// Mitsubishi GX Works2 project: TR3FB_sample_AnticollisionRead   PLC: Q03UDV
// TR3FBサンプルプログラム シリアル接続 アンチコリジョン制御

PROGRAM MAIN
VAR
  Initial_1 : P+TAKAYA-TR3-C24_Initial;
  Response_1 : P+TAKAYA-TR3-C24_Response;
  Inventory2_1 : P+TAKAYA-TR3-C24_Inventory2;
  ReadBytes_1 : P+TAKAYA-TR3-C24_ReadBytes;
  CallBuzzer_1 : P+TAKAYA-TR3-C24_CallBuzzer;
  SetTransmitSig_1 : P+TAKAYA-TR3-C24_SetTransmitSig;
END_VAR
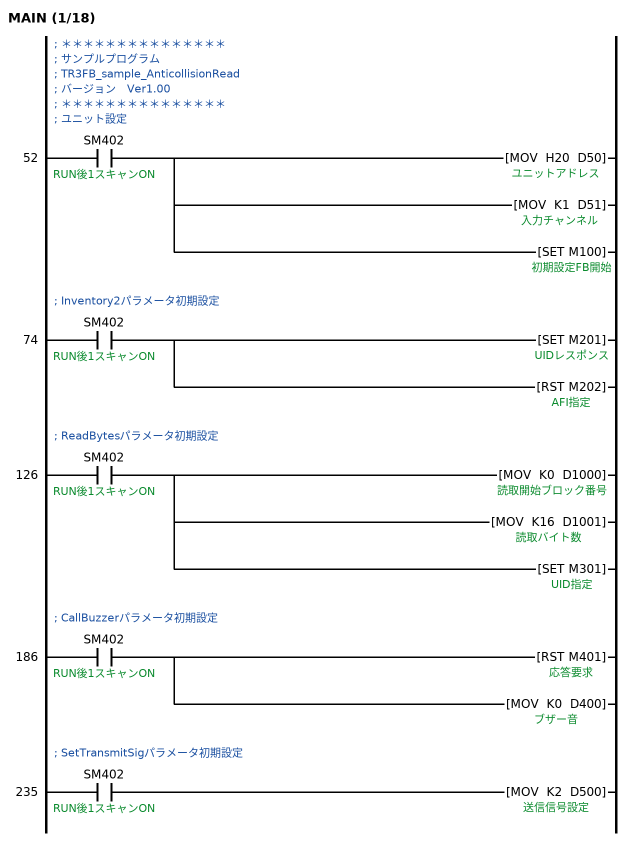
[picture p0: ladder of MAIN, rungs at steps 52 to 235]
; 
; ＊＊＊＊＊＊＊＊＊＊＊＊＊＊＊
; サンプルプログラム
; TR3FB_sample_AnticollisionRead
; バージョン　Ver1.00
; ＊＊＊＊＊＊＊＊＊＊＊＊＊＊＊
; ユニット設定
52    LD      SM402  ; RUN後1スキャンON
      MOV     H20 D50  ; ユニットアドレス
      MOV     K1 D51  ; 入力チャンネル
      SET     M100  ; 初期設定FB開始
; Inventory2パラメータ初期設定
74    LD      SM402  ; RUN後1スキャンON
      SET     M201  ; UIDレスポンス
        [note] UIDレスポンス：ON=UID数とUID
      RST     M202  ; AFI指定
        [note] AFI指定：OFF=AFI値を指定しない
; ReadBytesパラメータ初期設定
126   LD      SM402  ; RUN後1スキャンON
      MOV     K0 D1000  ; 読取開始ブロック番号
        [note] 読取開始ブロック番号=0
      MOV     K16 D1001  ; 読取バイト数
        [note] 読取バイト数=16
      SET     M301  ; UID指定
        [note] UID指定：ON=UIDを指定する
; CallBuzzerパラメータ初期設定
186   LD      SM402  ; RUN後1スキャンON
      RST     M401  ; 応答要求
        [note] 応答要求：OFF=応答を要求しない
      MOV     K0 D400  ; ブザー音
        [note] ブザー音=0/ピー
; SetTransmitSigパラメータ初期設定
235   LD      SM402  ; RUN後1スキャンON
      MOV     K2 D500  ; 送信信号設定
        [note] 送信信号設定：2=OFF→ON
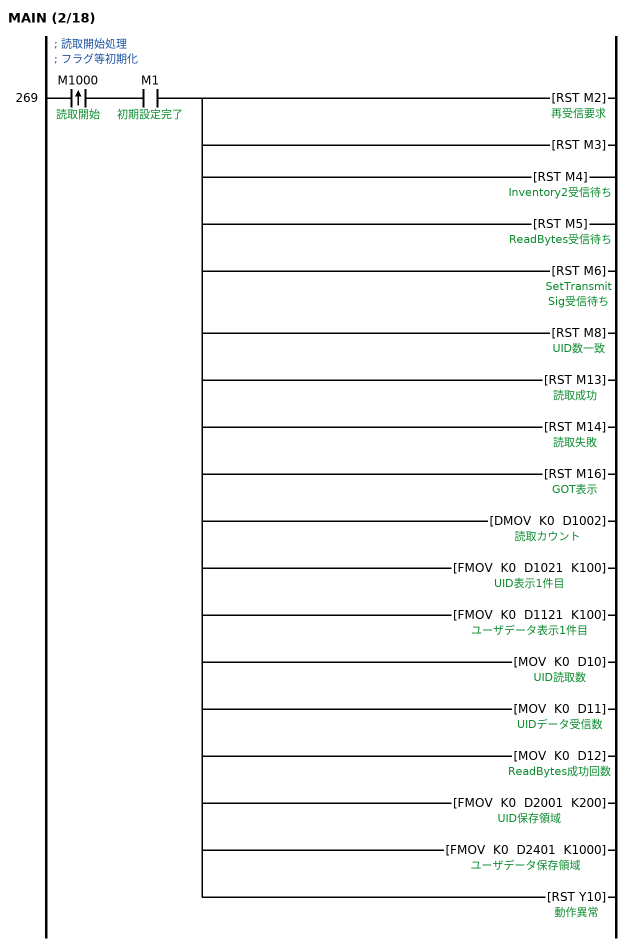
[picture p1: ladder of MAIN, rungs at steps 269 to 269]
; 読取開始処理
; フラグ等初期化
269   LDP     M1000  ; 読取開始
      AND     M1  ; 初期設定完了
      RST     M2  ; 再受信要求
        [note] 再受信要求フラグリセット
      RST     M3
        [note] 受信解析フラグリセット
      RST     M4  ; Inventory2受信待ち
        [note] Inventory2受信待ちフラグリセット
      RST     M5  ; ReadBytes受信待ち
        [note] ReadBytes受信待ちフラグリセット
      RST     M6  ; SetTransmitSig受信待ち
        [note] SetTrainsmitSigフラグリセット
      RST     M8  ; UID数一致
        [note] UID数一致フラグリセット
      RST     M13  ; 読取成功
        [note] 読取成功フラグリセット
      RST     M14  ; 読取失敗
        [note] 読取失敗フラグリセット
      RST     M16  ; GOT表示
        [note] GOT表示フラグリセット
      DMOV    K0 D1002  ; 読取カウント
        [note] GOT読取枚数表示クリア
      FMOV    K0 D1021 K100  ; UID表示1件目
        [note] GOT_UID表示領域クリア
      FMOV    K0 D1121 K100  ; ユーザデータ表示1件目
        [note] GOT_ユーザデータ表示領域クリア
      MOV     K0 D10  ; UID読取数
        [note] UID読取数クリア
      MOV     K0 D11  ; UIDデータ受信数
        [note] UIDデータ受信数クリア
      MOV     K0 D12  ; ReadBytes成功回数
        [note] ReadBytes成功回数クリア
      FMOV    K0 D2001 K200  ; UID保存領域
        [note] UID保存領域クリア
      FMOV    K0 D2401 K1000  ; ユーザデータ保存領域
        [note] ユーザデータ保存領域クリア
      RST     Y10  ; 動作異常
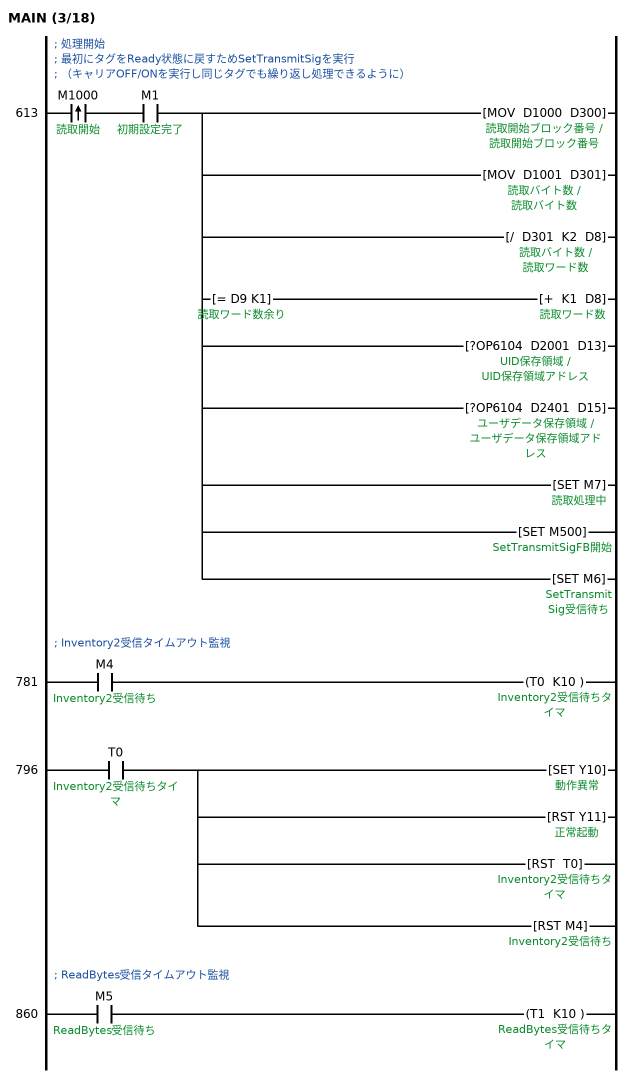
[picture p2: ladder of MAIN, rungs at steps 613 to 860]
; 処理開始
; 最初にタグをReady状態に戻すためSetTransmitSigを実行
; （キャリアOFF/ONを実行し同じタグでも繰り返し処理できるように）
613   LDP     M1000  ; 読取開始
      AND     M1  ; 初期設定完了
      MOV     D1000 D300  ; 読取開始ブロック番号
        [note] 読取開始ブロック番号再設定
      MOV     D1001 D301  ; 読取バイト数
        [note] 読取バイト数再設定
      /       D301 K2 D8  ; 読取ワード数
        [note] 読取バイト数から読取ワード数算出
      MPS
      AND=    D9 K1  ; 読取ワード数余り
      +       K1 D8
        [note] 余りがあれば1加える
      MPP
      ?OP6104 D2001 D13  ; UID保存領域アドレス
        [note] UID保存領域アドレス初期化
      ?OP6104 D2401 D15  ; ユーザデータ保存領域アドレス
        [note] ユーザデータ保存アドレス初期化
      SET     M7  ; 読取処理中
        [note] 読取処理中フラグセット
      SET     M500  ; SetTransmitSigFB開始
        [note] SetTransmitSig実行
      SET     M6  ; SetTransmitSig受信待ち
        [note] 受信待ちフラグセット
; Inventory2受信タイムアウト監視
781   LD      M4  ; Inventory2受信待ち
      OUT     T0 K10  ; Inventory2受信待ちタイマ
        [note] タイマ1秒に設定
796   LD      T0  ; Inventory2受信待ちタイマ
      SET     Y10  ; 動作異常
        [note] 動作異常：セット
      RST     Y11  ; 正常起動
        [note] 正常動作：リセット
      RST     T0  ; Inventory2受信待ちタイマ
        [note] タイマリセット
      RST     M4  ; Inventory2受信待ち
        [note] フラグリセット
; ReadBytes受信タイムアウト監視
860   LD      M5  ; ReadBytes受信待ち
      OUT     T1 K10  ; ReadBytes受信待ちタイマ
        [note] タイマ1秒に設定
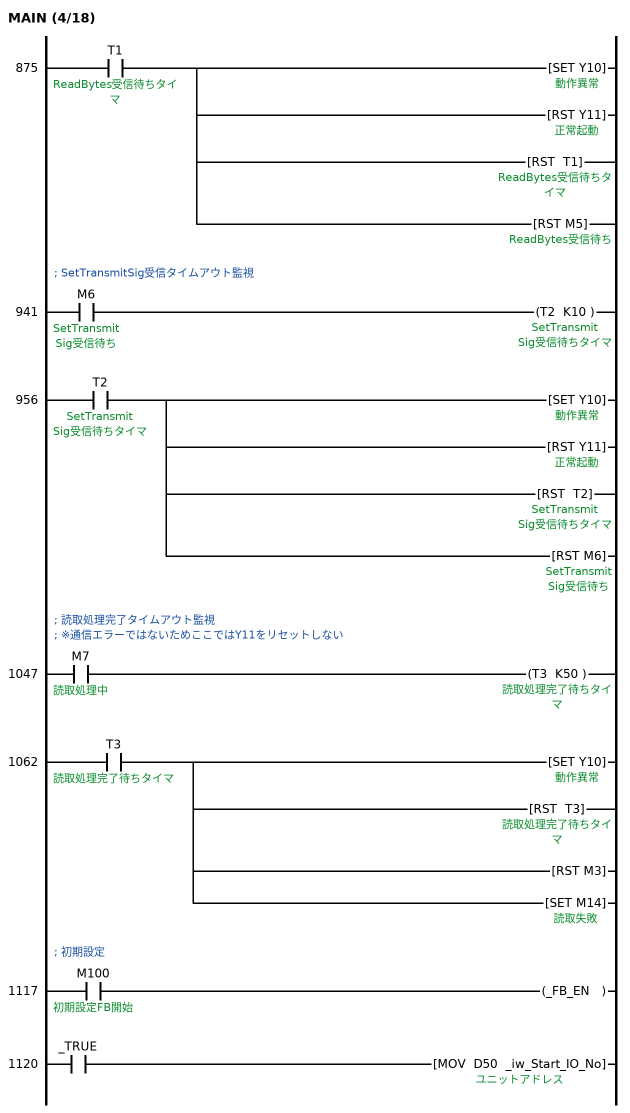
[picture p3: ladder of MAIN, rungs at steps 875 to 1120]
875   LD      T1  ; ReadBytes受信待ちタイマ
      SET     Y10  ; 動作異常
        [note] 動作異常：セット
      RST     Y11  ; 正常起動
        [note] 正常起動：リセット
      RST     T1  ; ReadBytes受信待ちタイマ
        [note] タイマリセット
      RST     M5  ; ReadBytes受信待ち
        [note] フラグリセット
; SetTransmitSig受信タイムアウト監視
941   LD      M6  ; SetTransmitSig受信待ち
      OUT     T2 K10  ; SetTransmitSig受信待ちタイマ
        [note] タイマ1秒に設定
956   LD      T2  ; SetTransmitSig受信待ちタイマ
      SET     Y10  ; 動作異常
        [note] 動作異常：セット
      RST     Y11  ; 正常起動
        [note] 正常起動：リセット
      RST     T2  ; SetTransmitSig受信待ちタイマ
        [note] タイマリセット
      RST     M6  ; SetTransmitSig受信待ち
        [note] フラグリセット
; 読取処理完了タイムアウト監視
; ※通信エラーではないためここではY11をリセットしない
1047  LD      M7  ; 読取処理中
      OUT     T3 K50  ; 読取処理完了待ちタイマ
        [note] タイマ5秒に設定
1062  LD      T3  ; 読取処理完了待ちタイマ
      SET     Y10  ; 動作異常
        [note] 動作異常：セット
      RST     T3  ; 読取処理完了待ちタイマ
        [note] タイマリセット
      RST     M3
        [note] フラグリセット
      SET     M14  ; 読取失敗
        [note] 読取失敗：セット
; FB BLK START P+TAKAYA-TR3-C24_Initial(Initial_1)
; 
; 初期設定
1117  LD      M100  ; 初期設定FB開始
      OUT     _FB_EN
1120  LD      _TRUE
      MOV     D50 _iw_Start_IO_No
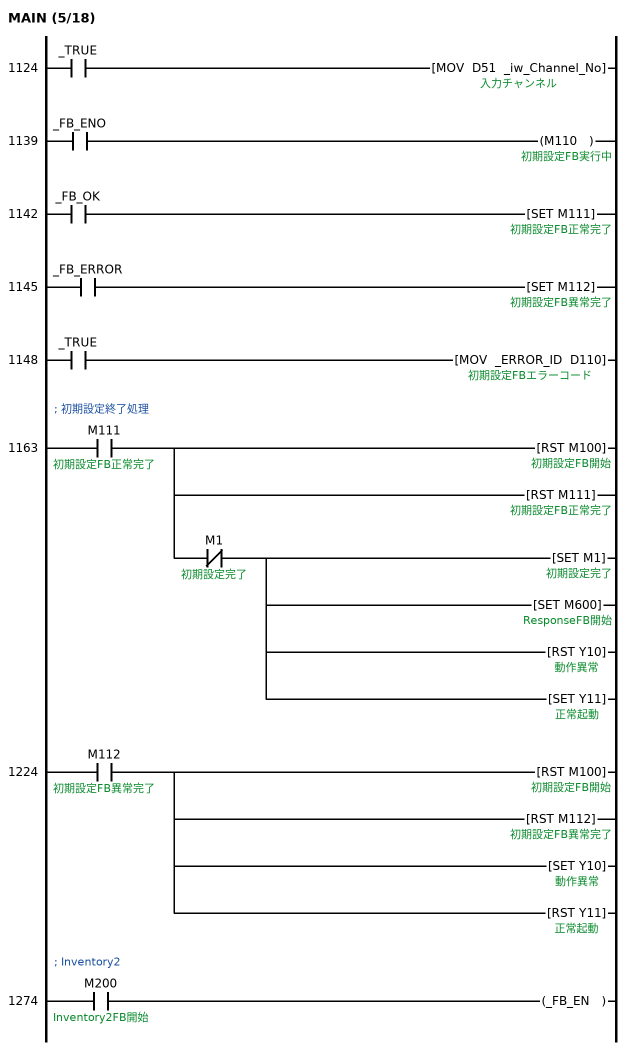
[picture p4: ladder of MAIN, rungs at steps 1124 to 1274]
1124  LD      _TRUE
      MOV     D51 _iw_Channel_No
; FB START
; FB_NAME P+TAKAYA-TR3-C24_Initial
; INSTANCE_NAME Initial_1
; FB IN_B:FB_EN
; FB OUT_FB_ENO:B
; FB IN_W:iw_Start_IO_No
; FB OUT_FB_OK:B
; FB IN_W:iw_Channel_No
; FB OUT_FB_ERROR:B
; FB OUT_ERROR_ID:W
; FB END
1139  LD      _FB_ENO
      OUT     M110  ; 初期設定FB実行中
1142  LD      _FB_OK
      SET     M111  ; 初期設定FB正常完了
1145  LD      _FB_ERROR
      SET     M112  ; 初期設定FB異常完了
1148  LD      _TRUE
      MOV     _ERROR_ID D110  ; 初期設定FBエラーコード
; FB BLK END
; 初期設定終了処理
1163  LD      M111  ; 初期設定FB正常完了
      RST     M100  ; 初期設定FB開始
        [note] FB動作停止
      RST     M111  ; 初期設定FB正常完了
        [note] フラグリセット
      ANI     M1  ; 初期設定完了
      SET     M1  ; 初期設定完了
        [note] 初期設定完了
      SET     M600  ; ResponseFB開始
        [note] 受信処理開始
      RST     Y10  ; 動作異常
        [note] 動作異常：リセット
      SET     Y11  ; 正常起動
        [note] 正常起動：セット
1224  LD      M112  ; 初期設定FB異常完了
      RST     M100  ; 初期設定FB開始
        [note] FB動作停止
      RST     M112  ; 初期設定FB異常完了
        [note] フラグリセット
      SET     Y10  ; 動作異常
        [note] 動作異常：セット
      RST     Y11  ; 正常起動
        [note] 動作正常：リセット
; FB BLK START P+TAKAYA-TR3-C24_Inventory2(Inventory2_1)
; Inventory2
1274  LD      M200  ; Inventory2FB開始
      OUT     _FB_EN
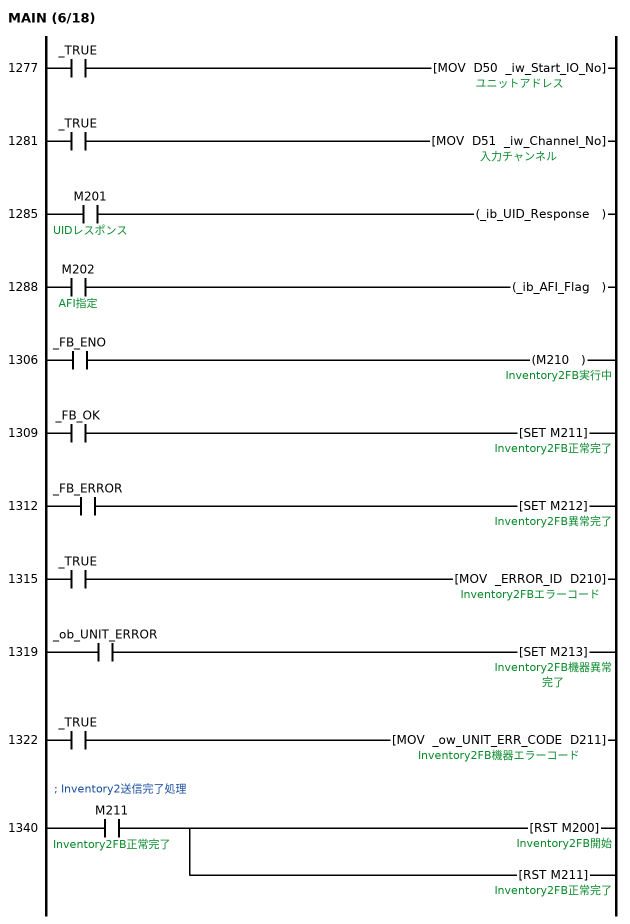
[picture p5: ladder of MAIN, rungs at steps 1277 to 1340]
1277  LD      _TRUE
      MOV     D50 _iw_Start_IO_No
1281  LD      _TRUE
      MOV     D51 _iw_Channel_No
1285  LD      M201  ; UIDレスポンス
      OUT     _ib_UID_Response
1288  LD      M202  ; AFI指定
      OUT     _ib_AFI_Flag
; FB START
; FB_NAME P+TAKAYA-TR3-C24_Inventory2
; INSTANCE_NAME Inventory2_1
; FB IN_B:FB_EN
; FB OUT_FB_ENO:B
; FB IN_W:iw_Start_IO_No
; FB OUT_FB_OK:B
; FB IN_W:iw_Channel_No
; FB OUT_FB_ERROR:B
; FB IN_B:ib_UID_Response
; FB OUT_ERROR_ID:W
; FB IN_B:ib_AFI_Flag
; FB OUT_ob_UNIT_ERROR:B
; FB OUT_ow_UNIT_ERR_CODE:W
; FB END
1306  LD      _FB_ENO
      OUT     M210  ; Inventory2FB実行中
1309  LD      _FB_OK
      SET     M211  ; Inventory2FB正常完了
1312  LD      _FB_ERROR
      SET     M212  ; Inventory2FB異常完了
1315  LD      _TRUE
      MOV     _ERROR_ID D210  ; Inventory2FBエラーコード
1319  LD      _ob_UNIT_ERROR
      SET     M213  ; Inventory2FB機器異常完了
1322  LD      _TRUE
      MOV     _ow_UNIT_ERR_CODE D211  ; Inventory2FB機器エラーコード
; FB BLK END
; Inventory2送信完了処理
1340  LD      M211  ; Inventory2FB正常完了
      RST     M200  ; Inventory2FB開始
        [note] FB動作停止
      RST     M211  ; Inventory2FB正常完了
        [note] フラグリセット
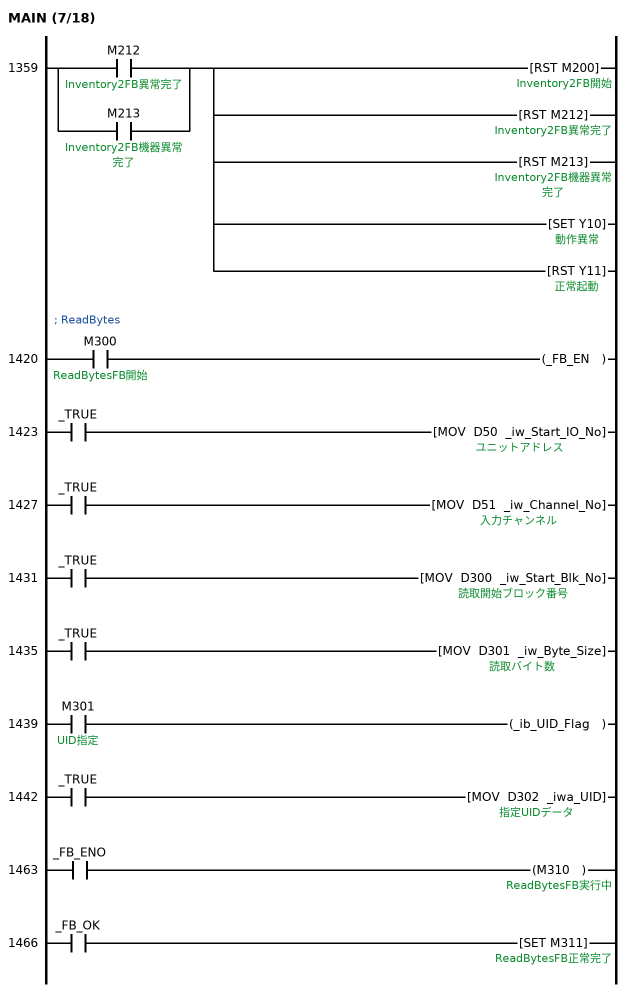
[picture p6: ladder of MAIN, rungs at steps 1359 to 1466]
1359  LD      M212  ; Inventory2FB異常完了
      OR      M213  ; Inventory2FB機器異常完了
      RST     M200  ; Inventory2FB開始
        [note] FB動作停止
      RST     M212  ; Inventory2FB異常完了
        [note] フラグリセット
      RST     M213  ; Inventory2FB機器異常完了
        [note] フラグリセット
      SET     Y10  ; 動作異常
        [note] 動作異常：セット
      RST     Y11  ; 正常起動
        [note] 正常起動：リセット
; FB BLK START P+TAKAYA-TR3-C24_ReadBytes(ReadBytes_1)
; ReadBytes
1420  LD      M300  ; ReadBytesFB開始
      OUT     _FB_EN
1423  LD      _TRUE
      MOV     D50 _iw_Start_IO_No
1427  LD      _TRUE
      MOV     D51 _iw_Channel_No
1431  LD      _TRUE
      MOV     D300 _iw_Start_Blk_No
1435  LD      _TRUE
      MOV     D301 _iw_Byte_Size
1439  LD      M301  ; UID指定
      OUT     _ib_UID_Flag
1442  LD      _TRUE
      MOV     D302 _iwa_UID  ; 指定UIDデータ
; FB START
; FB_NAME P+TAKAYA-TR3-C24_ReadBytes
; INSTANCE_NAME ReadBytes_1
; FB IN_B:FB_EN
; FB OUT_FB_ENO:B
; FB IN_W:iw_Start_IO_No
; FB OUT_FB_OK:B
; FB IN_W:iw_Channel_No
; FB OUT_FB_ERROR:B
; FB IN_W:iw_Start_Blk_No
; FB OUT_ERROR_ID:W
; FB IN_W:iw_Byte_Size
; FB OUT_ob_UNIT_ERROR:B
; FB IN_B:ib_UID_Flag
; FB OUT_ow_UNIT_ERR_CODE:W
; FB IN_W:iwa_UID
; FB END
1463  LD      _FB_ENO
      OUT     M310  ; ReadBytesFB実行中
1466  LD      _FB_OK
      SET     M311  ; ReadBytesFB正常完了
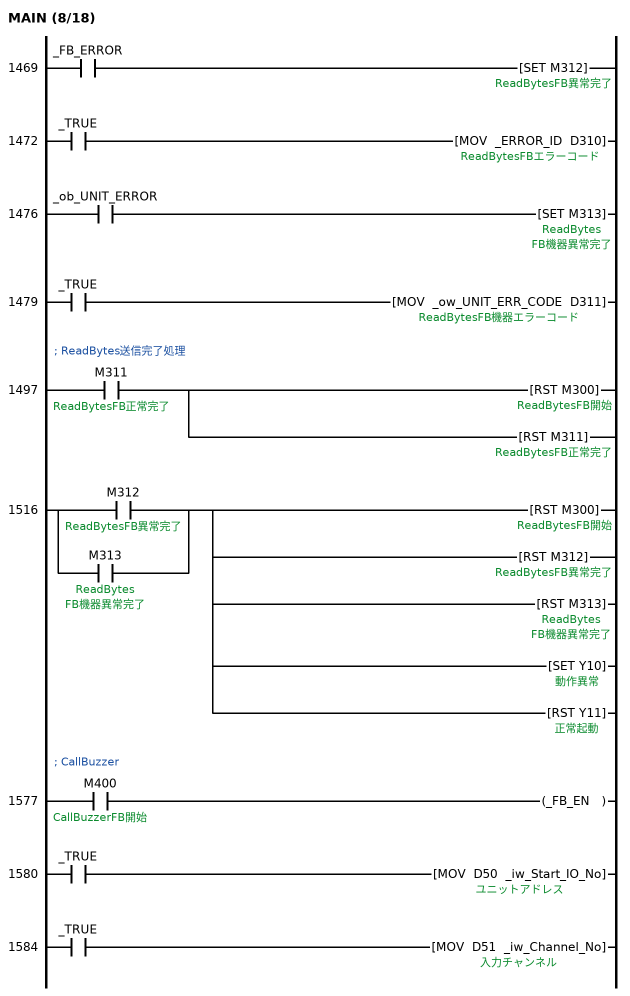
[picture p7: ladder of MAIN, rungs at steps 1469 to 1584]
1469  LD      _FB_ERROR
      SET     M312  ; ReadBytesFB異常完了
1472  LD      _TRUE
      MOV     _ERROR_ID D310  ; ReadBytesFBエラーコード
1476  LD      _ob_UNIT_ERROR
      SET     M313  ; ReadBytesFB機器異常完了
1479  LD      _TRUE
      MOV     _ow_UNIT_ERR_CODE D311  ; ReadBytesFB機器エラーコード
; FB BLK END
; ReadBytes送信完了処理
1497  LD      M311  ; ReadBytesFB正常完了
      RST     M300  ; ReadBytesFB開始
        [note] FB動作停止
      RST     M311  ; ReadBytesFB正常完了
        [note] フラグリセット
1516  LD      M312  ; ReadBytesFB異常完了
      OR      M313  ; ReadBytesFB機器異常完了
      RST     M300  ; ReadBytesFB開始
        [note] FB動作停止
      RST     M312  ; ReadBytesFB異常完了
        [note] フラグリセット
      RST     M313  ; ReadBytesFB機器異常完了
        [note] フラグリセット
      SET     Y10  ; 動作異常
        [note] 動作異常：セット
      RST     Y11  ; 正常起動
        [note] 正常起動：リセット
; FB BLK START P+TAKAYA-TR3-C24_CallBuzzer(CallBuzzer_1)
; CallBuzzer
1577  LD      M400  ; CallBuzzerFB開始
      OUT     _FB_EN
1580  LD      _TRUE
      MOV     D50 _iw_Start_IO_No
1584  LD      _TRUE
      MOV     D51 _iw_Channel_No
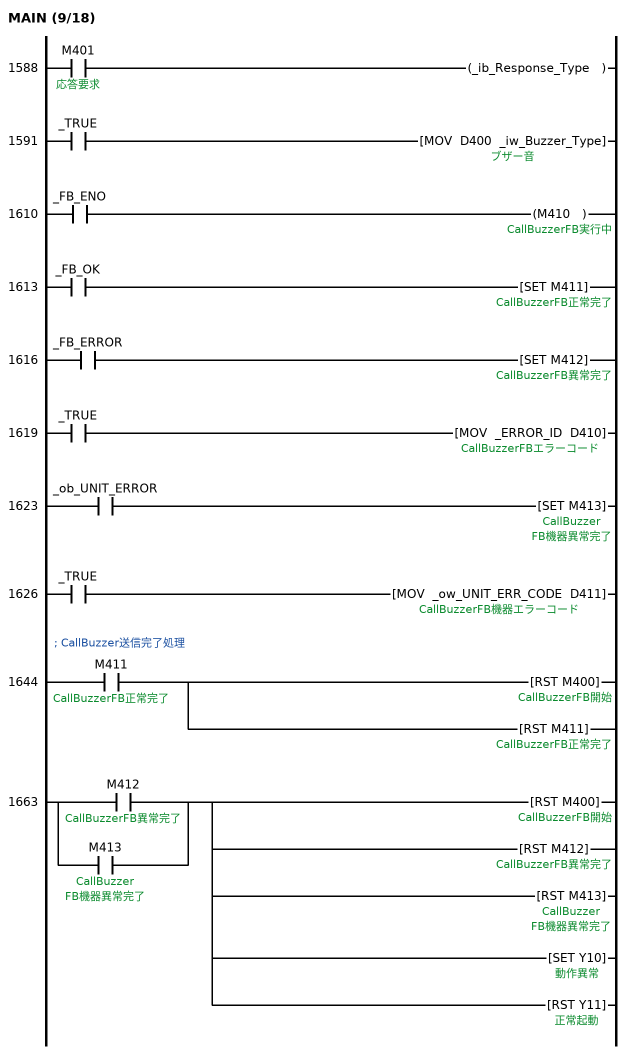
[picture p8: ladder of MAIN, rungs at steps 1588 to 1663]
1588  LD      M401  ; 応答要求
      OUT     _ib_Response_Type
1591  LD      _TRUE
      MOV     D400 _iw_Buzzer_Type
; FB START
; FB_NAME P+TAKAYA-TR3-C24_CallBuzzer
; INSTANCE_NAME CallBuzzer_1
; FB IN_B:FB_EN
; FB OUT_FB_ENO:B
; FB IN_W:iw_Start_IO_No
; FB OUT_FB_OK:B
; FB IN_W:iw_Channel_No
; FB OUT_FB_ERROR:B
; FB IN_B:ib_Response_Type
; FB OUT_ERROR_ID:W
; FB IN_W:iw_Buzzer_Type
; FB OUT_ob_UNIT_ERROR:B
; FB OUT_ow_UNIT_ERR_CODE:W
; FB END
1610  LD      _FB_ENO
      OUT     M410  ; CallBuzzerFB実行中
1613  LD      _FB_OK
      SET     M411  ; CallBuzzerFB正常完了
1616  LD      _FB_ERROR
      SET     M412  ; CallBuzzerFB異常完了
1619  LD      _TRUE
      MOV     _ERROR_ID D410  ; CallBuzzerFBエラーコード
1623  LD      _ob_UNIT_ERROR
      SET     M413  ; CallBuzzerFB機器異常完了
1626  LD      _TRUE
      MOV     _ow_UNIT_ERR_CODE D411  ; CallBuzzerFB機器エラーコード
; FB BLK END
; CallBuzzer送信完了処理
1644  LD      M411  ; CallBuzzerFB正常完了
      RST     M400  ; CallBuzzerFB開始
        [note] FB動作停止
      RST     M411  ; CallBuzzerFB正常完了
        [note] フラグリセット
1663  LD      M412  ; CallBuzzerFB異常完了
      OR      M413  ; CallBuzzerFB機器異常完了
      RST     M400  ; CallBuzzerFB開始
        [note] FB動作停止
      RST     M412  ; CallBuzzerFB異常完了
        [note] フラグリセット
      RST     M413  ; CallBuzzerFB機器異常完了
        [note] フラグリセット
      SET     Y10  ; 動作異常
        [note] 動作異常：セット
      RST     Y11  ; 正常起動
        [note] 正常起動：リセット
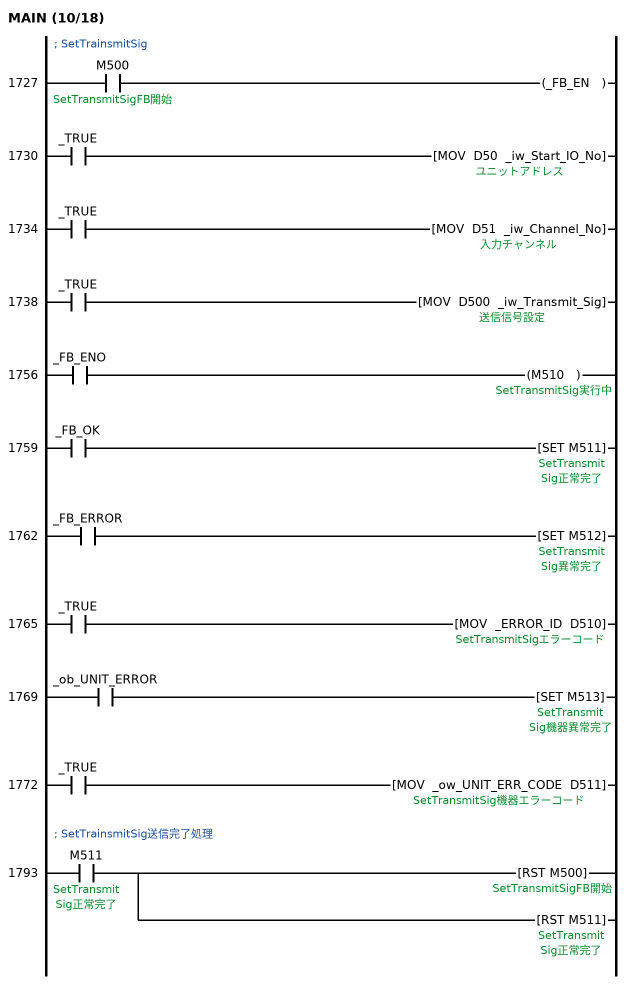
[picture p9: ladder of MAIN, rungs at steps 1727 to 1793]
; FB BLK START P+TAKAYA-TR3-C24_SetTransmitSig(SetTransmitSig_1)
; SetTrainsmitSig
1727  LD      M500  ; SetTransmitSigFB開始
      OUT     _FB_EN
1730  LD      _TRUE
      MOV     D50 _iw_Start_IO_No
1734  LD      _TRUE
      MOV     D51 _iw_Channel_No
1738  LD      _TRUE
      MOV     D500 _iw_Transmit_Sig
; FB START
; FB_NAME P+TAKAYA-TR3-C24_SetTransmitSig
; INSTANCE_NAME SetTransmitSig_1
; FB IN_B:FB_EN
; FB OUT_FB_ENO:B
; FB IN_W:iw_Start_IO_No
; FB OUT_FB_OK:B
; FB IN_W:iw_Channel_No
; FB OUT_FB_ERROR:B
; FB IN_W:iw_Transmit_Sig
; FB OUT_ERROR_ID:W
; FB OUT_ob_UNIT_ERROR:B
; FB OUT_ow_UNIT_ERR_CODE:W
; FB END
1756  LD      _FB_ENO
      OUT     M510  ; SetTransmitSig実行中
1759  LD      _FB_OK
      SET     M511  ; SetTransmitSig正常完了
1762  LD      _FB_ERROR
      SET     M512  ; SetTransmitSig異常完了
1765  LD      _TRUE
      MOV     _ERROR_ID D510  ; SetTransmitSigエラーコード
1769  LD      _ob_UNIT_ERROR
      SET     M513  ; SetTransmitSig機器異常完了
1772  LD      _TRUE
      MOV     _ow_UNIT_ERR_CODE D511  ; SetTransmitSig機器エラーコード
; FB BLK END
; SetTrainsmitSig送信完了処理
1793  LD      M511  ; SetTransmitSig正常完了
      RST     M500  ; SetTransmitSigFB開始
        [note] FB動作停止
      RST     M511  ; SetTransmitSig正常完了
        [note] フラグリセット
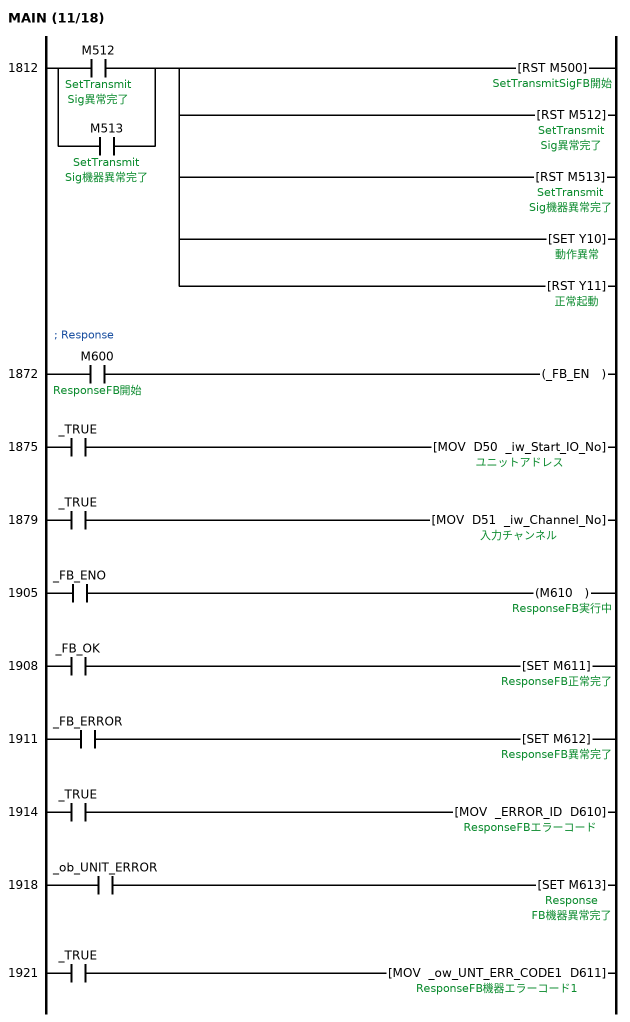
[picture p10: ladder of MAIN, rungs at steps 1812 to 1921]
1812  LD      M512  ; SetTransmitSig異常完了
      OR      M513  ; SetTransmitSig機器異常完了
      RST     M500  ; SetTransmitSigFB開始
        [note] FB動作停止
      RST     M512  ; SetTransmitSig異常完了
        [note] フラグリセット
      RST     M513  ; SetTransmitSig機器異常完了
        [note] フラグリセット
      SET     Y10  ; 動作異常
        [note] 動作異常：セット
      RST     Y11  ; 正常起動
        [note] 正常起動：リセット
; FB BLK START P+TAKAYA-TR3-C24_Response(Response_1)
; Response
1872  LD      M600  ; ResponseFB開始
      OUT     _FB_EN
1875  LD      _TRUE
      MOV     D50 _iw_Start_IO_No
1879  LD      _TRUE
      MOV     D51 _iw_Channel_No
; FB START
; FB_NAME P+TAKAYA-TR3-C24_Response
; INSTANCE_NAME Response_1
; FB IN_B:FB_EN
; FB OUT_FB_ENO:B
; FB IN_W:iw_Start_IO_No
; FB OUT_FB_OK:B
; FB IN_W:iw_Channel_No
; FB OUT_FB_ERROR:B
; FB OUT_ERROR_ID:W
; FB OUT_ob_UNIT_ERROR:B
; FB OUT_ow_UNT_ERR_CODE1:W
; FB OUT_ow_UNT_ERR_CODE2:W
; FB OUT_ow_RFID_Res_Type:W
; FB OUT_ow_RFID_ID:W
; FB OUT_ow_RFID_UID_Len:W
; FB OUT_ow_RFID_Data_Len:W
; FB OUT_ow_RFID_UII_Len:W
; FB OUT_owa_RFID_UID:W
; FB OUT_owa_RFID_Data:W
; FB OUT_owa_RFID_UII:W
; FB END
1905  LD      _FB_ENO
      OUT     M610  ; ResponseFB実行中
1908  LD      _FB_OK
      SET     M611  ; ResponseFB正常完了
1911  LD      _FB_ERROR
      SET     M612  ; ResponseFB異常完了
1914  LD      _TRUE
      MOV     _ERROR_ID D610  ; ResponseFBエラーコード
1918  LD      _ob_UNIT_ERROR
      SET     M613  ; ResponseFB機器異常完了
1921  LD      _TRUE
      MOV     _ow_UNT_ERR_CODE1 D611  ; ResponseFB機器エラーコード1
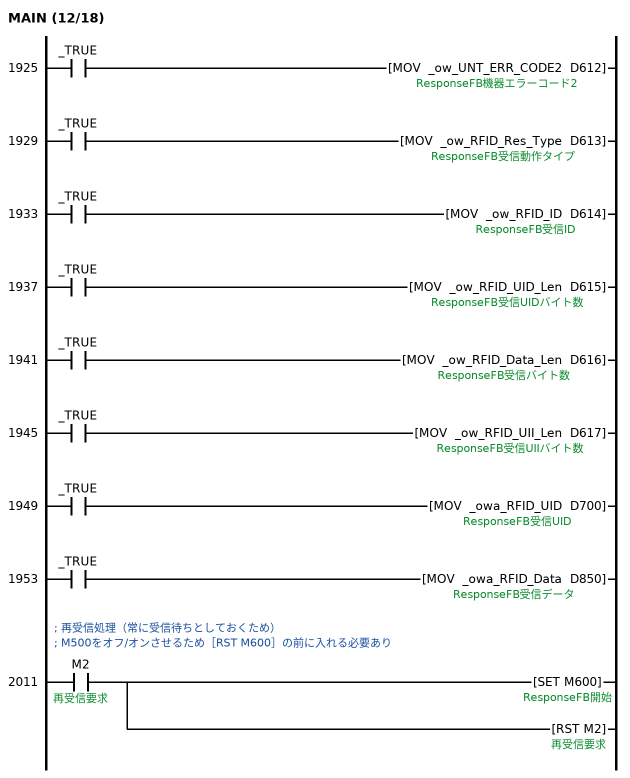
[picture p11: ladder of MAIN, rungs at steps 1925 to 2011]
1925  LD      _TRUE
      MOV     _ow_UNT_ERR_CODE2 D612  ; ResponseFB機器エラーコード2
1929  LD      _TRUE
      MOV     _ow_RFID_Res_Type D613  ; ResponseFB受信動作タイプ
1933  LD      _TRUE
      MOV     _ow_RFID_ID D614  ; ResponseFB受信ID
1937  LD      _TRUE
      MOV     _ow_RFID_UID_Len D615  ; ResponseFB受信UIDバイト数
1941  LD      _TRUE
      MOV     _ow_RFID_Data_Len D616  ; ResponseFB受信バイト数
1945  LD      _TRUE
      MOV     _ow_RFID_UII_Len D617  ; ResponseFB受信UIIバイト数
1949  LD      _TRUE
      MOV     _owa_RFID_UID D700  ; ResponseFB受信UID
1953  LD      _TRUE
      MOV     _owa_RFID_Data D850  ; ResponseFB受信データ
; FB BLK END
; 再受信処理（常に受信待ちとしておくため）
; M500をオフ/オンさせるため［RST M600］の前に入れる必要あり
2011  LD      M2  ; 再受信要求
      SET     M600  ; ResponseFB開始
        [note] ResponseFB開始
      RST     M2  ; 再受信要求
        [note] フラグリセット
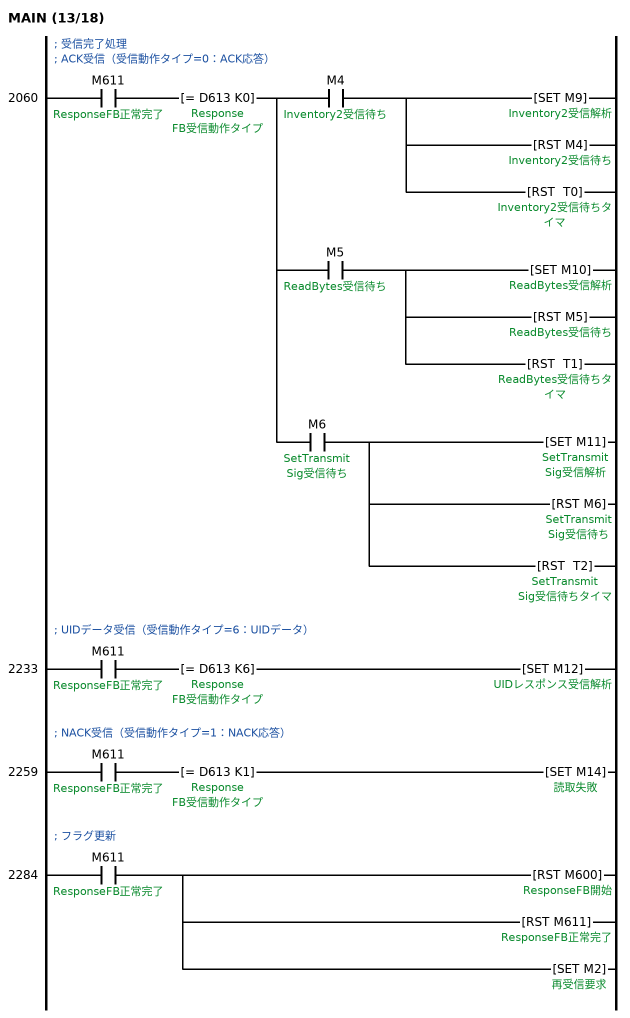
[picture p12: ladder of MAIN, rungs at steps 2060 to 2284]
; 受信完了処理
; ACK受信（受信動作タイプ=0：ACK応答）
2060  LD      M611  ; ResponseFB正常完了
      AND=    D613 K0  ; ResponseFB受信動作タイプ
      MPS
      AND     M4  ; Inventory2受信待ち
      SET     M9  ; Inventory2受信解析
        [note] Inventory2受信解析：セット
      RST     M4  ; Inventory2受信待ち
        [note] フラグリセット
      RST     T0  ; Inventory2受信待ちタイマ
        [note] 正常処理のためタイマリセット
      MRD
      AND     M5  ; ReadBytes受信待ち
      SET     M10  ; ReadBytes受信解析
        [note] ReadBytes受信解析：セット
      RST     M5  ; ReadBytes受信待ち
        [note] フラグリセット
      RST     T1  ; ReadBytes受信待ちタイマ
        [note] 正常処理のためタイマリセット
      MPP
      AND     M6  ; SetTransmitSig受信待ち
      SET     M11  ; SetTransmitSig受信解析
        [note] SetTransmitSig受信解析：セット
      RST     M6  ; SetTransmitSig受信待ち
        [note] フラグリセット
      RST     T2  ; SetTransmitSig受信待ちタイマ
        [note] 正常処理のためタイマクリア
; UIDデータ受信（受信動作タイプ=6：UIDデータ）
2233  LD      M611  ; ResponseFB正常完了
      AND=    D613 K6  ; ResponseFB受信動作タイプ
      SET     M12  ; UIDレスポンス受信解析
; NACK受信（受信動作タイプ=1：NACK応答）
2259  LD      M611  ; ResponseFB正常完了
      AND=    D613 K1  ; ResponseFB受信動作タイプ
      SET     M14  ; 読取失敗
        [note] 読取失敗フラグ：セット
; フラグ更新
2284  LD      M611  ; ResponseFB正常完了
      RST     M600  ; ResponseFB開始
        [note] FB動作停止
      RST     M611  ; ResponseFB正常完了
        [note] フラグリセット
      SET     M2  ; 再受信要求
        [note] 再受信要求フラグ：セット
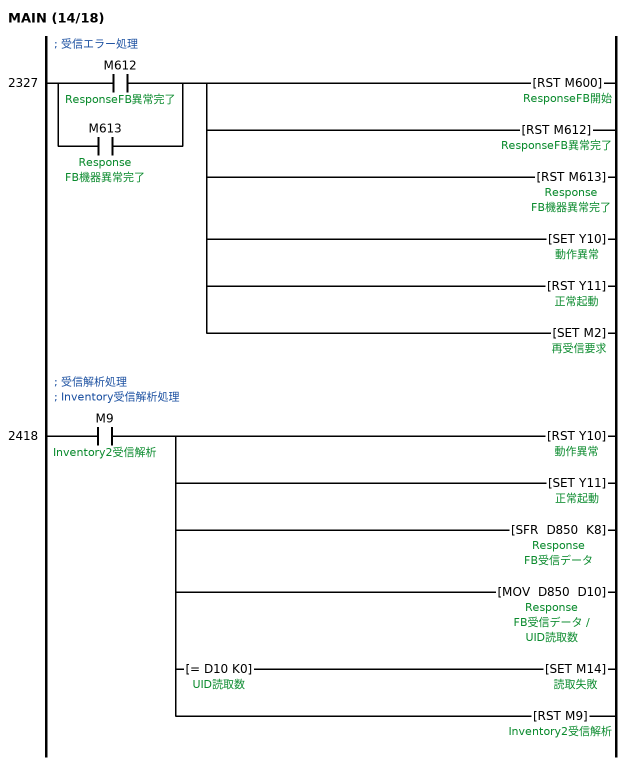
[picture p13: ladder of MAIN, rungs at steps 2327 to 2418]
; 受信エラー処理
2327  LD      M612  ; ResponseFB異常完了
      OR      M613  ; ResponseFB機器異常完了
      RST     M600  ; ResponseFB開始
        [note] FB動作停止
      RST     M612  ; ResponseFB異常完了
        [note] フラグリセット
      RST     M613  ; ResponseFB機器異常完了
        [note] フラグリセット
      SET     Y10  ; 動作異常
        [note] 動作異常：セット
      RST     Y11  ; 正常起動
        [note] 正常起動：リセット
      SET     M2  ; 再受信要求
        [note] 再受信要求フラグ：セット
; 
; 受信解析処理
; Inventory受信解析処理
2418  LD      M9  ; Inventory2受信解析
      RST     Y10  ; 動作異常
        [note] 動作異常：リセット
      SET     Y11  ; 正常起動
        [note] 正常動作：セット
      SFR     D850 K8
        [note] 受信データ2バイト目がUID読取数
      MOV     D850 D10
        [note] UID読取数設定
      MPS
      AND=    D10 K0  ; UID読取数
      SET     M14  ; 読取失敗
        [note] UID数=0のACKで読取失敗
      MPP
      RST     M9  ; Inventory2受信解析
        [note] フラグリセット
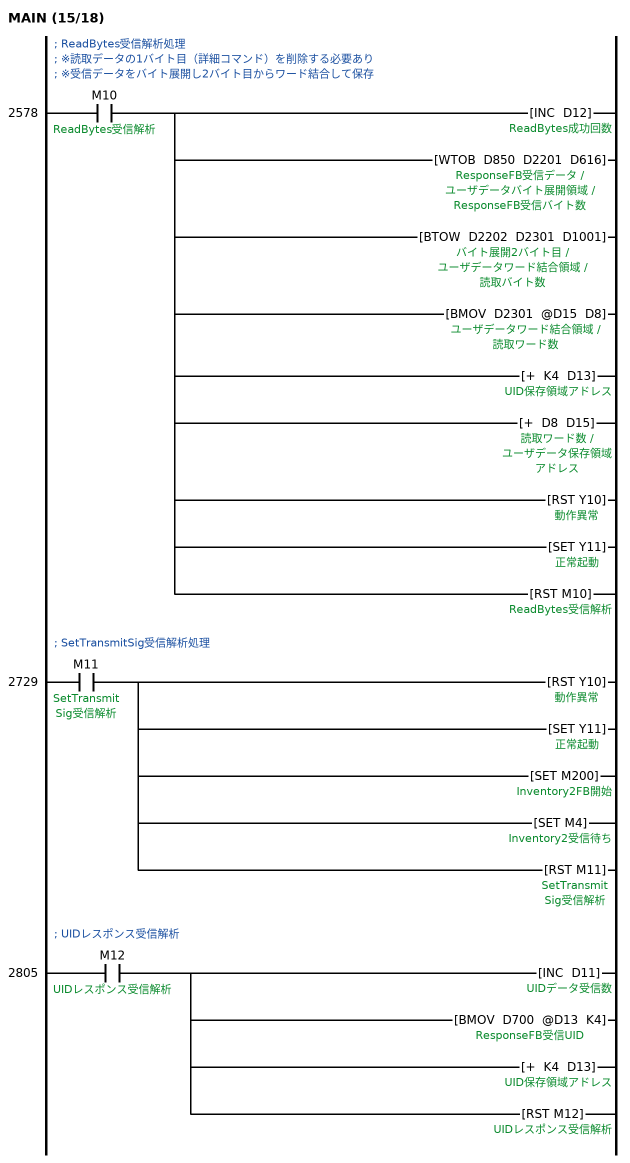
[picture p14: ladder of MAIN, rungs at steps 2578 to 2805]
; ReadBytes受信解析処理
; ※読取データの1バイト目（詳細コマンド）を削除する必要あり
; ※受信データをバイト展開し2バイト目からワード結合して保存
2578  LD      M10  ; ReadBytes受信解析
      INC     D12
        [note] 成功回数+1
      WTOB    D850 D2201 D616  ; ユーザデータバイト展開領域
        [note] 受信データをバイト展開
      BTOW    D2202 D2301 D1001  ; バイト展開2バイト目 / ユーザデータワード結合領域
        [note] 2バイト目から再度ワード結合
      BMOV    D2301 @D15 D8
        [note] 読取データを保存
      +       K4 D13
        [note] ReadBytesの指定UIDアドレスを次へ
      +       D8 D15
        [note] ユーザデータ保存先アドレスを次へ
      RST     Y10  ; 動作異常
        [note] 動作異常：リセット
      SET     Y11  ; 正常起動
        [note] 正常動作：セット
      RST     M10  ; ReadBytes受信解析
        [note] フラグリセット
; SetTransmitSig受信解析処理
2729  LD      M11  ; SetTransmitSig受信解析
      RST     Y10  ; 動作異常
        [note] 動作異常：リセット
      SET     Y11  ; 正常起動
        [note] 正常動作：セット
      SET     M200  ; Inventory2FB開始
        [note] Inventory2実行
      SET     M4  ; Inventory2受信待ち
        [note] Inventory2受信待ちフラグ：セット
      RST     M11  ; SetTransmitSig受信解析
        [note] フラグリセット
; UIDレスポンス受信解析
2805  LD      M12  ; UIDレスポンス受信解析
      INC     D11
        [note] UIDデータ受信数+1
      BMOV    D700 @D13 K4
        [note] UIDデータを保存
      +       K4 D13
        [note] UID保存領域アドレス+4
      RST     M12  ; UIDレスポンス受信解析
        [note] フラグリセット
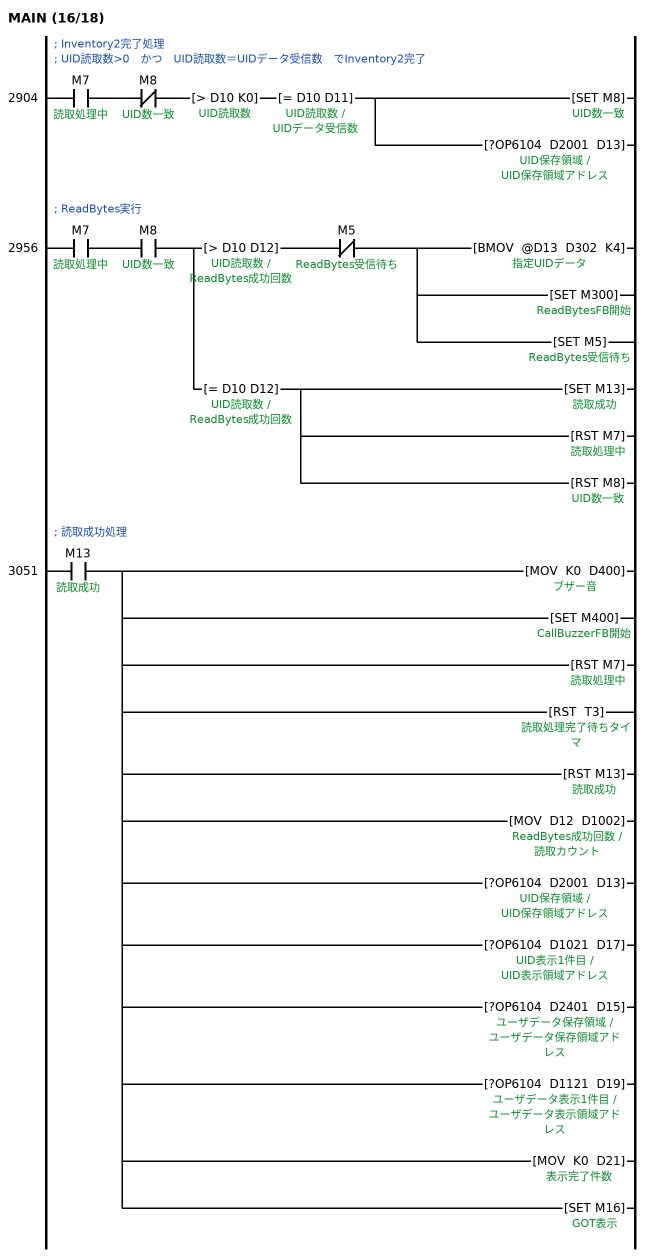
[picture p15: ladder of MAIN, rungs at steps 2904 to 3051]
; Inventory2完了処理
; UID読取数>0　かつ　UID読取数＝UIDデータ受信数　でInventory2完了
2904  LD      M7  ; 読取処理中
      ANI     M8  ; UID数一致
      AND>    D10 K0  ; UID読取数
      AND=    D10 D11  ; UID読取数 / UIDデータ受信数
      SET     M8  ; UID数一致
        [note] UID数一致フラグ：セット
      ?OP6104 D2001 D13
        [note] UID保存領域アドレスを元に戻す
; ReadBytes実行
2956  LD      M7  ; 読取処理中
      AND     M8  ; UID数一致
      MPS
      AND>    D10 D12  ; UID読取数 / ReadBytes成功回数
      ANI     M5  ; ReadBytes受信待ち
      BMOV    @D13 D302 K4
        [note] 指定UIDを設定
      SET     M300  ; ReadBytesFB開始
        [note] ReadBytes実行
      SET     M5  ; ReadBytes受信待ち
        [note] ReadBytes受信待ちフラグ：セット
      MPP
      AND=    D10 D12  ; UID読取数 / ReadBytes成功回数
      SET     M13  ; 読取成功
        [note] 読取成功フラグ：セット
      RST     M7  ; 読取処理中
        [note] フラグリセット
      RST     M8  ; UID数一致
        [note] フラグリセット
; 読取成功処理
3051  LD      M13  ; 読取成功
      MOV     K0 D400
        [note] ブザー音=0/ピー
      SET     M400  ; CallBuzzerFB開始
        [note] CallBuzzer実行
      RST     M7  ; 読取処理中
        [note] フラグリセット
      RST     T3  ; 読取処理完了待ちタイマ
        [note] タイマリセット
      RST     M13  ; 読取成功
        [note] フラグリセット
      MOV     D12 D1002
        [note] 読取カウント更新
      ?OP6104 D2001 D13
        [note] UID保存領域アドレス先頭指定
      ?OP6104 D1021 D17  ; UID表示領域アドレス
        [note] UID表示領域アドレス先頭指定
      ?OP6104 D2401 D15
        [note] ユーザ保存領域アドレス先頭指定
      ?OP6104 D1121 D19  ; ユーザデータ表示領域アドレス
        [note] ユーザ表示領域アドレス先頭指定
      MOV     K0 D21  ; 表示完了件数
        [note] 表示完了件数クリア
      SET     M16  ; GOT表示
        [note] GOT表示フラグ：セット
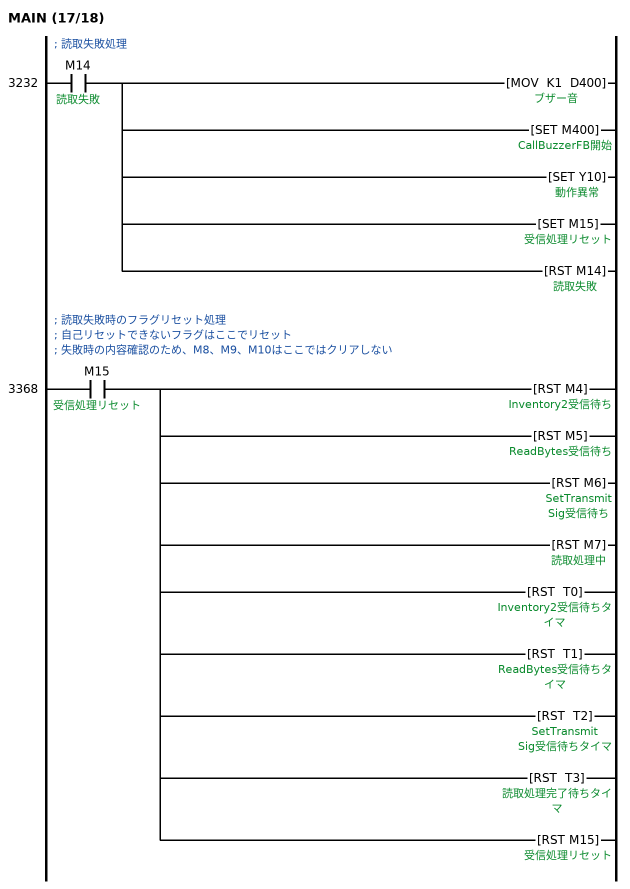
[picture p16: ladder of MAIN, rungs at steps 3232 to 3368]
; 読取失敗処理
3232  LD      M14  ; 読取失敗
      MOV     K1 D400
        [note] ブザー音=1/ピッピッピ
      SET     M400  ; CallBuzzerFB開始
        [note] CallBuzzer実行
      SET     Y10  ; 動作異常
        [note] 動作異常：セット
      SET     M15  ; 受信処理リセット
        [note] 受信処理リセットフラグ：セット
      RST     M14  ; 読取失敗
        [note] フラグリセット
; 読取失敗時のフラグリセット処理
; 自己リセットできないフラグはここでリセット
; 失敗時の内容確認のため、M8、M9、M10はここではクリアしない
3368  LD      M15  ; 受信処理リセット
      RST     M4  ; Inventory2受信待ち
        [note] フラグリセット
      RST     M5  ; ReadBytes受信待ち
        [note] フラグリセット
      RST     M6  ; SetTransmitSig受信待ち
        [note] フラグリセット
      RST     M7  ; 読取処理中
        [note] フラグリセット
      RST     T0  ; Inventory2受信待ちタイマ
      RST     T1  ; ReadBytes受信待ちタイマ
        [note] タイマリセット
      RST     T2  ; SetTransmitSig受信待ちタイマ
        [note] タイマリセット
      RST     T3  ; 読取処理完了待ちタイマ
        [note] タイマリセット
      RST     M15  ; 受信処理リセット
        [note] フラグリセット
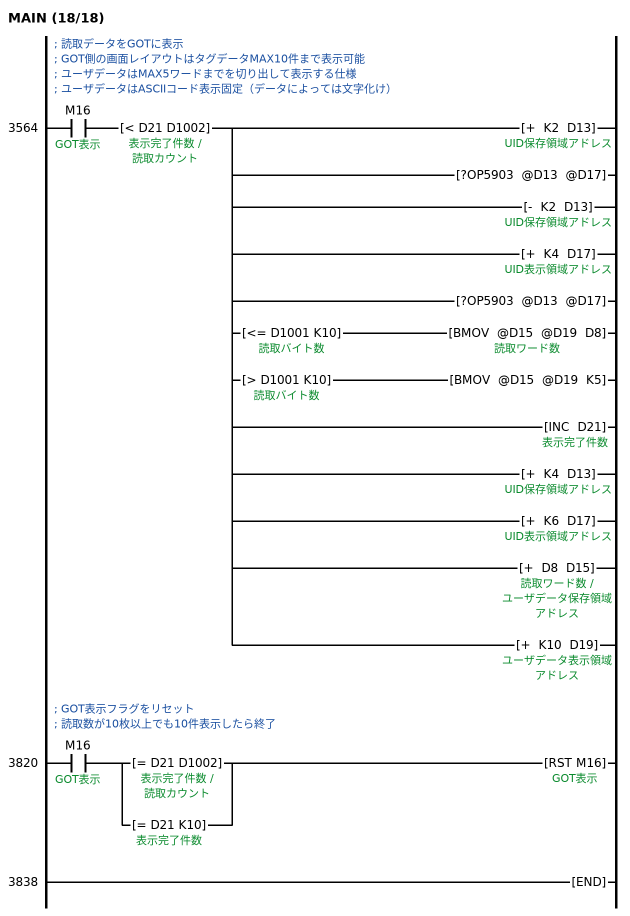
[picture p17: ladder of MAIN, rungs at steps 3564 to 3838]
; 読取データをGOTに表示
; GOT側の画面レイアウトはタグデータMAX10件まで表示可能
; ユーザデータはMAX5ワードまでを切り出して表示する仕様
; ユーザデータはASCIIコード表示固定（データによっては文字化け）
3564  LD      M16  ; GOT表示
      AND<    D21 D1002  ; 表示完了件数 / 読取カウント
      +       K2 D13
        [note] UID保存アドレスを上位側に移動
      ?OP5903 @D13 @D17
        [note] UID表示/上位4バイト
      -       K2 D13
        [note] UID保存アドレスを下位側に戻す
      +       K4 D17
        [note] UID表示アドレス+4
      ?OP5903 @D13 @D17
        [note] UID表示/下位4バイト
      MPS
      AND<=   D1001 K10  ; 読取バイト数
      BMOV    @D15 @D19 D8
        [note] ユーザデータ表示：5ワード以下
      MRD
      AND>    D1001 K10  ; 読取バイト数
      BMOV    @D15 @D19 K5
        [note] ユーザデータ表示：5ワード超
      MPP
      INC     D21
        [note] 表示完了件数+1
      +       K4 D13
        [note] UID保存領域アドレス+4
      +       K6 D17
        [note] UID表示領域アドレス+6
      +       D8 D15
        [note] ユーザデータ保存アドレスを次へ
      +       K10 D19
        [note] ユーザデータ表示アドレスを次へ
; GOT表示フラグをリセット
; 読取数が10枚以上でも10件表示したら終了
3820  LD      M16  ; GOT表示
      LD=     D21 D1002  ; 表示完了件数 / 読取カウント
      OR=     D21 K10  ; 表示完了件数
      ANB
      RST     M16  ; GOT表示
        [note] フラグリセット
3838  END
END_PROGRAM

FUNCTION_BLOCK P+TAKAYA-TR3-C24_Initial  // 初期設定
VAR_INPUT
  FB_EN : BOOL;  (* 実行命令 *)
  iw_Start_IO_No : INT;  (* ユニット装着XYアドレス *)
  iw_Channel_No : INT;  (* 入力チャンネル *)
END_VAR
VAR_OUTPUT
  FB_ENO : BOOL;  (* 実行状態 *)
  FB_OK : BOOL;  (* 正常完了 *)
  FB_ERROR : BOOL;  (* 異常完了フラグ *)
  ERROR_ID : INT;  (* エラーコード *)
END_VAR
VAR
  vb_Program_Init : BOOL;  (* プログラム実行前初期化 *)
  vb_Check_Input : BOOL;  (* 入力範囲判定 *)
  vb_Module_Init : BOOL;  (* ユニット初期化 *)
  vb_Program_End : BOOL;  (* FB終了処理内部フラグ *)
  vb_Tmp_OK : BOOL;  (* FB完了内部フラグ *)
  vb_Tmp_Error : BOOL;  (* エラー内部フラグ *)
  vw_Start_IO_No_Tmp : INT;  (* ユニット装着XYアドレス内部 *)
  vw_Channel_No_Tmp : INT;  (* 入力チャンネル内部 *)
  vw_ZTmp1 : INT;  (* Zデバイス1内部 *)
  vw_ZTmp2 : INT;  (* Zデバイス2内部 *)
END_VAR
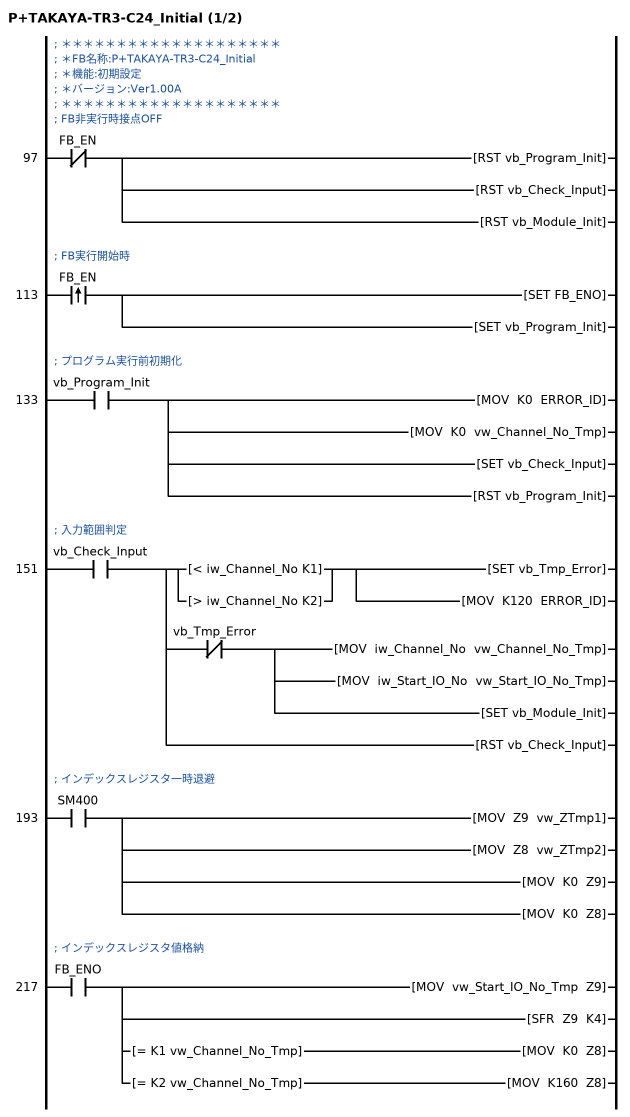
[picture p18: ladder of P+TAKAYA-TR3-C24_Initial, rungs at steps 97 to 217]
; ＊＊＊＊＊＊＊＊＊＊＊＊＊＊＊＊＊＊＊＊
; ＊FB名称:P+TAKAYA-TR3-C24_Initial
; ＊機能:初期設定
; ＊バージョン:Ver1.00A
; ＊＊＊＊＊＊＊＊＊＊＊＊＊＊＊＊＊＊＊＊
; FB非実行時接点OFF
97    LDI     FB_EN
      RST     vb_Program_Init
      RST     vb_Check_Input
      RST     vb_Module_Init
; FB実行開始時
113   LDP     FB_EN
      SET     FB_ENO
      SET     vb_Program_Init
; プログラム実行前初期化
133   LD      vb_Program_Init
      MOV     K0 ERROR_ID
      MOV     K0 vw_Channel_No_Tmp
      SET     vb_Check_Input
      RST     vb_Program_Init
; 入力範囲判定
151   LD      vb_Check_Input
      MPS
      LD<     iw_Channel_No K1
      OR>     iw_Channel_No K2
      ANB
      SET     vb_Tmp_Error
      MOV     K120 ERROR_ID
      MRD
      ANI     vb_Tmp_Error
      MOV     iw_Channel_No vw_Channel_No_Tmp
      MOV     iw_Start_IO_No vw_Start_IO_No_Tmp
      SET     vb_Module_Init
      MPP
      RST     vb_Check_Input
; インデックスレジスタ一時退避
193   LD      SM400
      MOV     Z9 vw_ZTmp1
      MOV     Z8 vw_ZTmp2
      MOV     K0 Z9
      MOV     K0 Z8
; インデックスレジスタ値格納
217   LD      FB_ENO
      MOV     vw_Start_IO_No_Tmp Z9
      SFR     Z9 K4
      MPS
      AND=    K1 vw_Channel_No_Tmp
      MOV     K0 Z8
      MPP
      AND=    K2 vw_Channel_No_Tmp
      MOV     K160 Z8
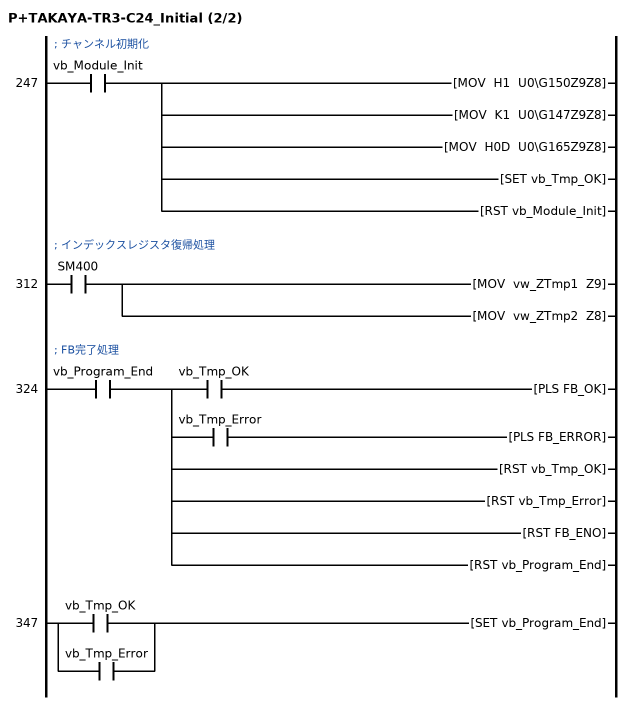
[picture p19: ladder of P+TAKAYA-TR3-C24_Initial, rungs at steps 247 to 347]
; チャンネル初期化
247   LD      vb_Module_Init
      MOV     H1 U0\G150Z9Z8
        [note] バイト単位指定
      MOV     K1 U0\G147Z9Z8
        [note] DC制御指定
      MOV     H0D U0\G165Z9Z8
        [note] 受信終了コード
      SET     vb_Tmp_OK
      RST     vb_Module_Init
; インデックスレジスタ復帰処理
312   LD      SM400
      MOV     vw_ZTmp1 Z9
      MOV     vw_ZTmp2 Z8
; FB完了処理
324   LD      vb_Program_End
      MPS
      AND     vb_Tmp_OK
      PLS     FB_OK
      MRD
      AND     vb_Tmp_Error
      PLS     FB_ERROR
      MPP
      RST     vb_Tmp_OK
      RST     vb_Tmp_Error
      RST     FB_ENO
      RST     vb_Program_End
347   LD      vb_Tmp_OK
      OR      vb_Tmp_Error
      SET     vb_Program_End
END_FUNCTION_BLOCK

FUNCTION_BLOCK P+TAKAYA-TR3-C24_Response  // 受信設定
VAR_INPUT
  FB_EN : BOOL;  (* 実行命令 *)
  iw_Start_IO_No : INT;  (* ユニット装着XYアドレス *)
END_VAR
VAR_OUTPUT
  FB_ENO : BOOL;  (* 実行状態 *)
  FB_OK : BOOL;  (* 正常完了 *)
  FB_ERROR : BOOL;  (* 異常完了フラグ *)
  ERROR_ID : INT;  (* エラーコード *)
  ob_UNIT_ERROR : BOOL;  (* 機器異常完了フラグ *)
  ow_UNT_ERR_CODE1 : INT;  (* 機器エラーコード1 *)
  ow_UNT_ERR_CODE2 : INT;  (* 機器エラーコード2 *)
  ow_RFID_Res_Type : INT;  (* 受信動作タイプ *)
  ow_RFID_ID : INT;  (* 受信ID *)
  ow_RFID_UID_Len : INT;  (* 受信UIDバイト数 *)
  ow_RFID_Data_Len : INT;  (* 受信バイト数 *)
  ow_RFID_UII_Len : INT;  (* 受信UIIバイト数 *)
  owa_RFID_UID : INT;  (* 受信UID *)
  owa_RFID_Data : INT;  (* 受信データ *)
  owa_RFID_UII : INT;  (* 受信UII *)
END_VAR
VAR
  vb_Tmp_OK : BOOL;  (* 正常完了内部フラグ *)
  vb_Tmp_Error : BOOL;  (* 異常完了内部フラグ *)
  vb_Tmp_Unit_Error : BOOL;  (* 機器異常完了内部フラグ *)
  vb_Program_Init : BOOL;  (* プログラム実行前初期化 *)
  vb_Check_Input : BOOL;  (* 入力範囲判定 *)
  vb_Check_Cmd : BOOL;  (* 受信コマンドチェック *)
  vb_UID_Cmd : BOOL;  (* UIDコマンド受信 *)
  vb_EPC_Cmd : BOOL;  (* EPCコマンド受信 *)
  vb_Other_Cmd : BOOL;  (* Otherコマンド受信 *)
  vb_Program_End : BOOL;  (* FB終了処理 *)
  vb_Receiving : BOOL;  (* 受信中フラグ *)
  vw_ZTmp1 : INT;  (* Zデバイス1内部 *)
  vd_DTmp1 : DINT;  (* 内部Dデバイス1 *)
  vd_DTmp2 : DINT;  (* 内部Dデバイス2 *)
  vd_DTmp3 : DINT;  (* 内部Dデバイス3 *)
  vd_DTmp4 : DINT;  (* 内部Dデバイス4 *)
  vba_Rcv : ARRAY [0..2] OF BOOL;  (* 受信処理 *)
  vb_Rcv_End : BOOL;  (* 受信処理終了 *)
  vb_Fin_Rcv : BOOL;  (* コマンド全データ受信終了 *)
  vd_Rcv_Pos : DINT;  (* 受信バッファ読出し位置 *)
  vwa_Rcv_Buf : ARRAY [0..130] OF INT;  (* 受信バッファ(ワード単位) *)
  vwa_Rcv_Data_Byte : ARRAY [0..261] OF INT;  (* 受信バッファ(バイト単位) *)
  vw_Received_Len : INT;  (* 受信済みデータ長 *)
  vw_Trans_Len : INT;  (* 受信データ長 *)
  vw_Fin_Rcv_Len : INT;  (* 受信データ長計算用 *)
  vw_Sum_Len : INT;  (* サム値計算用データ長 *)
  vw_Rcv_Sum : INT;  (* 受信サム値 *)
  vw_Channel_No_Tmp : INT;  (* 入力チャンネル内部 *)
  vw_Start_IO_No_Tmp : INT;  (* ユニット装着XYアドレス内部 *)
  vwa_Ctrl_Data : ARRAY [0..3] OF INT;  (* ダミーコントロールデータ *)
  vd_Calc_Dword : DINT;  (* ダブルワード計算用 *)
  vw_Etx_Ofs : INT;  (* ETXオフセット *)
  vw_Chk_TID_Len : INT;  (* TIDデータ長計算用 *)
END_VAR
VAR_INPUT
  iw_Channel_No : INT;  (* 入力チャンネル *)
END_VAR
VAR
  vw_ZTmp2 : INT;  (* Zデバイス2内部 *)
  vwa_Chk_Sum : ARRAY [0..1] OF INT;  (* サム計算値 *)
END_VAR
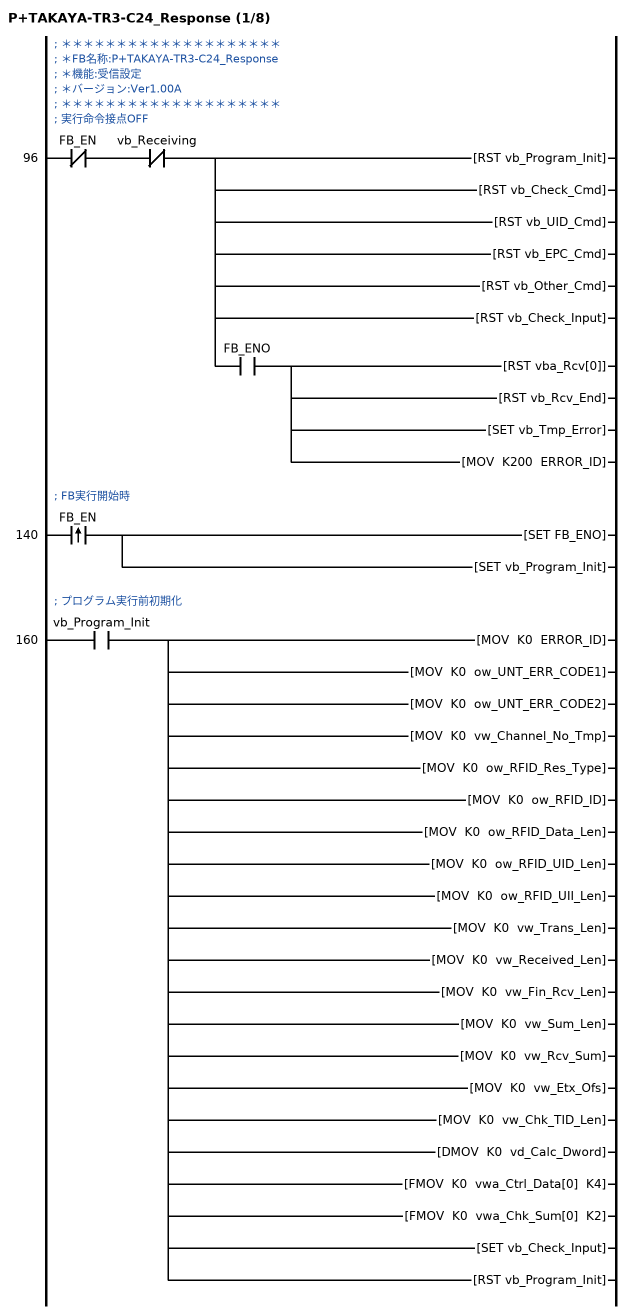
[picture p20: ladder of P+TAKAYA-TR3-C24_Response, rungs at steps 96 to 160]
; ＊＊＊＊＊＊＊＊＊＊＊＊＊＊＊＊＊＊＊＊
; ＊FB名称:P+TAKAYA-TR3-C24_Response
; ＊機能:受信設定
; ＊バージョン:Ver1.00A
; ＊＊＊＊＊＊＊＊＊＊＊＊＊＊＊＊＊＊＊＊
; 実行命令接点OFF
96    LDI     FB_EN
      ANI     vb_Receiving
      RST     vb_Program_Init
      RST     vb_Check_Cmd
      RST     vb_UID_Cmd
      RST     vb_EPC_Cmd
      RST     vb_Other_Cmd
      RST     vb_Check_Input
      AND     FB_ENO
      RST     vba_Rcv[0]
        [note] FB実行中強制終了
      RST     vb_Rcv_End
      SET     vb_Tmp_Error
      MOV     K200 ERROR_ID
; FB実行開始時
140   LDP     FB_EN
      SET     FB_ENO
      SET     vb_Program_Init
; プログラム実行前初期化
160   LD      vb_Program_Init
      MOV     K0 ERROR_ID
      MOV     K0 ow_UNT_ERR_CODE1
      MOV     K0 ow_UNT_ERR_CODE2
      MOV     K0 vw_Channel_No_Tmp
      MOV     K0 ow_RFID_Res_Type
      MOV     K0 ow_RFID_ID
      MOV     K0 ow_RFID_Data_Len
      MOV     K0 ow_RFID_UID_Len
      MOV     K0 ow_RFID_UII_Len
      MOV     K0 vw_Trans_Len
      MOV     K0 vw_Received_Len
      MOV     K0 vw_Fin_Rcv_Len
      MOV     K0 vw_Sum_Len
      MOV     K0 vw_Rcv_Sum
      MOV     K0 vw_Etx_Ofs
      MOV     K0 vw_Chk_TID_Len
      DMOV    K0 vd_Calc_Dword
      FMOV    K0 vwa_Ctrl_Data[0] K4
      FMOV    K0 vwa_Chk_Sum[0] K2
      SET     vb_Check_Input
      RST     vb_Program_Init
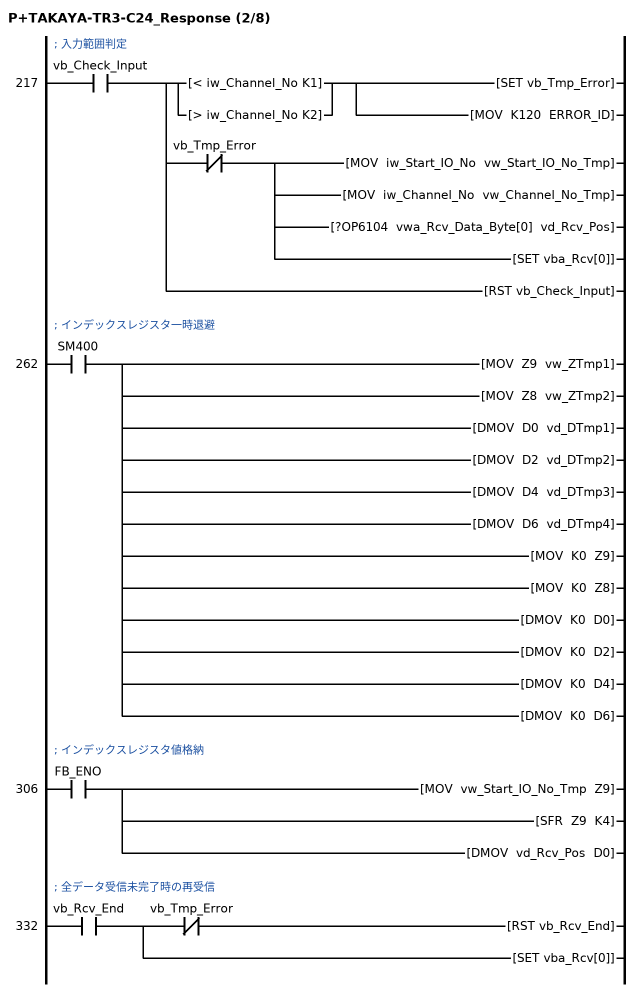
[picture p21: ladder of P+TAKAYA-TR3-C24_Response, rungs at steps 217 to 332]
; 入力範囲判定
217   LD      vb_Check_Input
      MPS
      LD<     iw_Channel_No K1
      OR>     iw_Channel_No K2
      ANB
      SET     vb_Tmp_Error
      MOV     K120 ERROR_ID
      MRD
      ANI     vb_Tmp_Error
      MOV     iw_Start_IO_No vw_Start_IO_No_Tmp
      MOV     iw_Channel_No vw_Channel_No_Tmp
      ?OP6104 vwa_Rcv_Data_Byte[0] vd_Rcv_Pos
      SET     vba_Rcv[0]
      MPP
      RST     vb_Check_Input
; インデックスレジスタ一時退避
262   LD      SM400
      MOV     Z9 vw_ZTmp1
      MOV     Z8 vw_ZTmp2
      DMOV    D0 vd_DTmp1
      DMOV    D2 vd_DTmp2
      DMOV    D4 vd_DTmp3
      DMOV    D6 vd_DTmp4
      MOV     K0 Z9
      MOV     K0 Z8
      DMOV    K0 D0
      DMOV    K0 D2
      DMOV    K0 D4
      DMOV    K0 D6
; インデックスレジスタ値格納
306   LD      FB_ENO
      MOV     vw_Start_IO_No_Tmp Z9
      SFR     Z9 K4
      DMOV    vd_Rcv_Pos D0
; 全データ受信未完了時の再受信
332   LD      vb_Rcv_End
      MPS
      ANI     vb_Tmp_Error
      RST     vb_Rcv_End
      MPP
      SET     vba_Rcv[0]
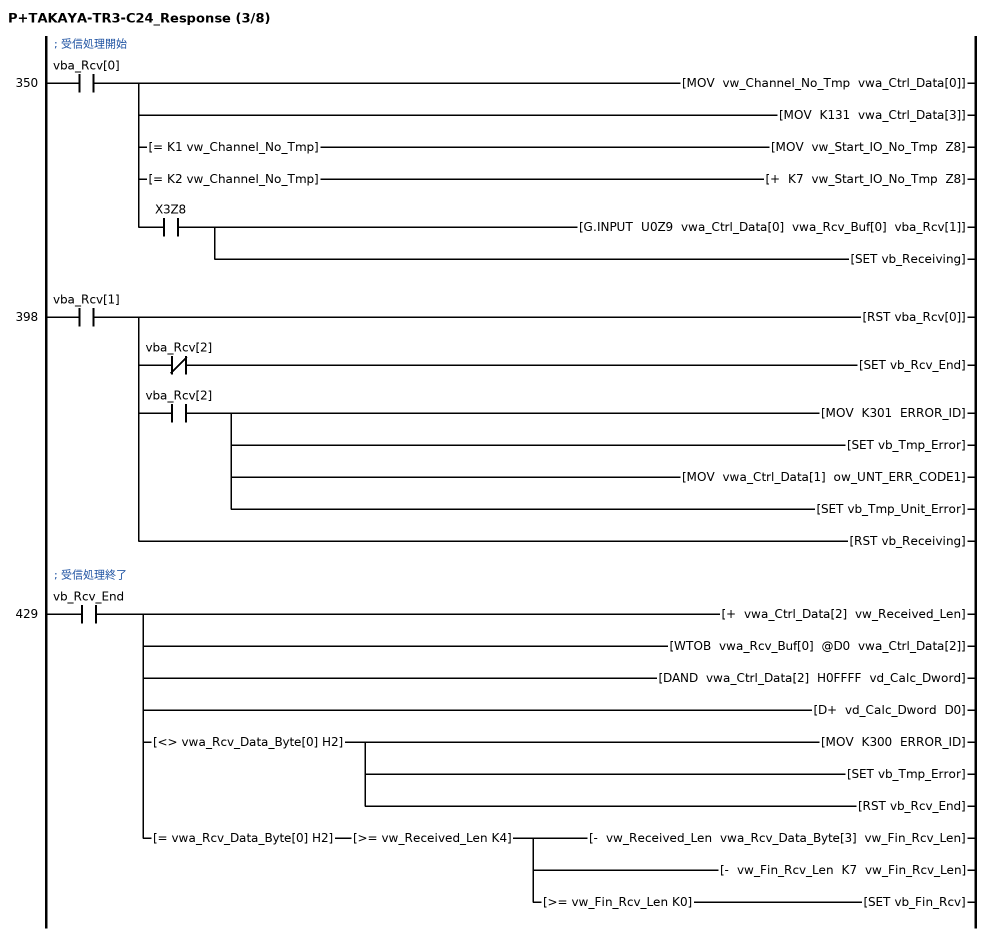
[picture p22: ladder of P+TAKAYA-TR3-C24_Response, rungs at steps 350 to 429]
; 受信処理開始
350   LD      vba_Rcv[0]
      MOV     vw_Channel_No_Tmp vwa_Ctrl_Data[0]
      MOV     K131 vwa_Ctrl_Data[3]
        [note] 受信データの許容ワード数
      MPS
      AND=    K1 vw_Channel_No_Tmp
      MOV     vw_Start_IO_No_Tmp Z8
      MRD
      AND=    K2 vw_Channel_No_Tmp
      +       K7 vw_Start_IO_No_Tmp Z8
      MPP
      AND     X3Z8
      G.INPUT U0Z9 vwa_Ctrl_Data[0] vwa_Rcv_Buf[0] vba_Rcv[1]
      SET     vb_Receiving
398   LD      vba_Rcv[1]
      RST     vba_Rcv[0]
      MPS
      ANI     vba_Rcv[2]
      SET     vb_Rcv_End
      MRD
      AND     vba_Rcv[2]
      MOV     K301 ERROR_ID
      SET     vb_Tmp_Error
      MOV     vwa_Ctrl_Data[1] ow_UNT_ERR_CODE1
      SET     vb_Tmp_Unit_Error
      MPP
      RST     vb_Receiving
; 受信処理終了
429   LD      vb_Rcv_End
      +       vwa_Ctrl_Data[2] vw_Received_Len
      WTOB    vwa_Rcv_Buf[0] @D0 vwa_Ctrl_Data[2]
      DAND    vwa_Ctrl_Data[2] H0FFFF vd_Calc_Dword
      D+      vd_Calc_Dword D0
      MPS
      AND<>   vwa_Rcv_Data_Byte[0] H2
      MOV     K300 ERROR_ID
      SET     vb_Tmp_Error
      RST     vb_Rcv_End
      MPP
      AND=    vwa_Rcv_Data_Byte[0] H2
      AND>=   vw_Received_Len K4
      -       vw_Received_Len vwa_Rcv_Data_Byte[3] vw_Fin_Rcv_Len
      -       vw_Fin_Rcv_Len K7 vw_Fin_Rcv_Len
      AND>=   vw_Fin_Rcv_Len K0
      SET     vb_Fin_Rcv
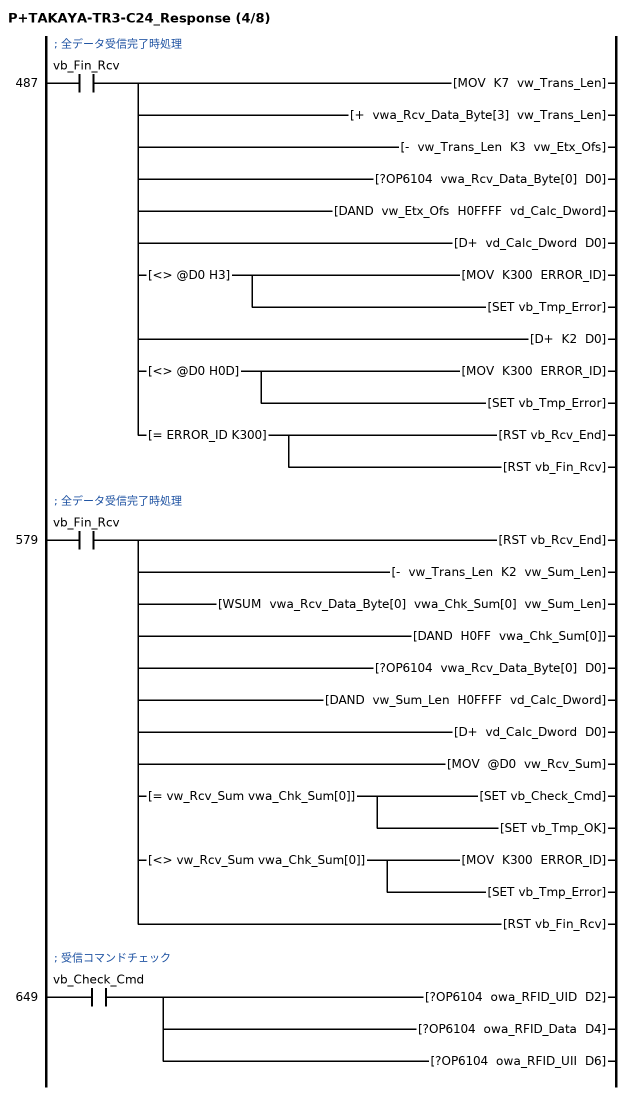
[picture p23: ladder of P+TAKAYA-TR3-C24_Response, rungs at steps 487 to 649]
; 全データ受信完了時処理
487   LD      vb_Fin_Rcv
      MOV     K7 vw_Trans_Len
      +       vwa_Rcv_Data_Byte[3] vw_Trans_Len
      -       vw_Trans_Len K3 vw_Etx_Ofs
      ?OP6104 vwa_Rcv_Data_Byte[0] D0
      DAND    vw_Etx_Ofs H0FFFF vd_Calc_Dword
      D+      vd_Calc_Dword D0
      MPS
      AND<>   @D0 H3
      MOV     K300 ERROR_ID
        [note] ETX値確認
      SET     vb_Tmp_Error
      MPP
      D+      K2 D0
        [note] CR値 =ETX値 + 2ワード
      MPS
      AND<>   @D0 H0D
      MOV     K300 ERROR_ID
        [note] CR値確認
      SET     vb_Tmp_Error
      MPP
      AND=    ERROR_ID K300
      RST     vb_Rcv_End
      RST     vb_Fin_Rcv
; 全データ受信完了時処理
579   LD      vb_Fin_Rcv
      RST     vb_Rcv_End
      -       vw_Trans_Len K2 vw_Sum_Len
        [note] SUMチェック処理
      WSUM    vwa_Rcv_Data_Byte[0] vwa_Chk_Sum[0] vw_Sum_Len
      DAND    H0FF vwa_Chk_Sum[0]
      ?OP6104 vwa_Rcv_Data_Byte[0] D0
      DAND    vw_Sum_Len H0FFFF vd_Calc_Dword
      D+      vd_Calc_Dword D0
      MOV     @D0 vw_Rcv_Sum
      MPS
      AND=    vw_Rcv_Sum vwa_Chk_Sum[0]
      SET     vb_Check_Cmd
      SET     vb_Tmp_OK
      MRD
      AND<>   vw_Rcv_Sum vwa_Chk_Sum[0]
      MOV     K300 ERROR_ID
      SET     vb_Tmp_Error
      MPP
      RST     vb_Fin_Rcv
; 受信コマンドチェック
649   LD      vb_Check_Cmd
      ?OP6104 owa_RFID_UID D2
      ?OP6104 owa_RFID_Data D4
      ?OP6104 owa_RFID_UII D6
; 受信コマンドチェック
672   LD      vb_Check_Cmd
      MOV     vwa_Rcv_Data_Byte[1] ow_RFID_ID
        [note] 受信IDの設定
      MOV     K255 ow_RFID_Res_Type
        [note] 受信動作タイプの設定
      MPS
      AND=    vwa_Rcv_Data_Byte[2] H30
      MOV     K0 ow_RFID_Res_Type
      MRD
      AND=    vwa_Rcv_Data_Byte[2] H31
      MOV     K1 ow_RFID_Res_Type
      MRD
      AND=    vwa_Rcv_Data_Byte[2] H64
      MOV     K2 ow_RFID_Res_Type
      AND=    vwa_Rcv_Data_Byte[12] H42
      AND=    vwa_Rcv_Data_Byte[13] H52
      MOV     K5 ow_RFID_Res_Type
      MRD
      AND=    vwa_Rcv_Data_Byte[2] H4C
      MOV     K3 ow_RFID_Res_Type
      MRD
      AND=    vwa_Rcv_Data_Byte[2] H44
      MOV     K4 ow_RFID_Res_Type
      AND=    vwa_Rcv_Data_Byte[4] H42
      AND=    vwa_Rcv_Data_Byte[5] H52
      MOV     K5 ow_RFID_Res_Type
      MRD
      AND=    vwa_Rcv_Data_Byte[2] H49
      MOV     K6 ow_RFID_Res_Type
      MRD
      AND=    vwa_Rcv_Data_Byte[2] H6C
      AND=    vwa_Rcv_Data_Byte[4] H7
      MOV     K7 ow_RFID_Res_Type
      MPP
      AND=    vwa_Rcv_Data_Byte[2] H6C
      AND=    vwa_Rcv_Data_Byte[4] H8
      MOV     K8 ow_RFID_Res_Type
768   LD      vb_Check_Cmd
      MPS
      AND=    vwa_Rcv_Data_Byte[2] H30
      LD=     vwa_Rcv_Data_Byte[4] H1
      OR=     vwa_Rcv_Data_Byte[4] H2B
      ANB
      SET     vb_UID_Cmd
      MRD
      LD=     vwa_Rcv_Data_Byte[2] H49
      OR=     vwa_Rcv_Data_Byte[2] H4C
      OR=     vwa_Rcv_Data_Byte[2] H64
      ANB
      SET     vb_UID_Cmd
      MRD
      AND=    vwa_Rcv_Data_Byte[2] H6C
      SET     vb_EPC_Cmd
      MRD
      ANI     vb_UID_Cmd
      ANI     vb_EPC_Cmd
      SET     vb_Other_Cmd
      MPP
      RST     vb_Check_Cmd
; UIDを含むコマンドの出力ラベル設定
831   LD      vb_UID_Cmd
      MOV     K8 ow_RFID_UID_Len
        [note] 受信UIDバイト数の設定
      MOV     vwa_Rcv_Data_Byte[3] ow_RFID_Data_Len
        [note] 受信バイト数の設定
      MPS
      AND<>   ow_RFID_Res_Type K0
      AND<>   ow_RFID_Res_Type K6
      -       ow_RFID_UID_Len ow_RFID_Data_Len
      MPP
      MOV     K0 ow_RFID_UII_Len
        [note] 受信UIIバイト数の設定
      AND=    vwa_Rcv_Data_Byte[2] H30
      BTOW    vwa_Rcv_Data_Byte[6] @D2 ow_RFID_UID_Len
      BTOW    vwa_Rcv_Data_Byte[4] @D4 ow_RFID_Data_Len
898   LD      vb_UID_Cmd
      AND=    vwa_Rcv_Data_Byte[2] H49
      BTOW    vwa_Rcv_Data_Byte[5] @D2 ow_RFID_UID_Len
      BTOW    vwa_Rcv_Data_Byte[4] @D4 ow_RFID_Data_Len
911   LD      vb_UID_Cmd
      MPS
      LD=     vwa_Rcv_Data_Byte[2] H4C
      OR=     vwa_Rcv_Data_Byte[2] H64
      ANB
      BTOW    vwa_Rcv_Data_Byte[4] @D2 ow_RFID_UID_Len
      BTOW    vwa_Rcv_Data_Byte[12] @D4 ow_RFID_Data_Len
      MPP
      RST     vb_UID_Cmd
; EPCコマンドの出力ラベル設定
948   LD      vb_EPC_Cmd
      MOV     vwa_Rcv_Data_Byte[5] ow_RFID_UII_Len
      BTOW    vwa_Rcv_Data_Byte[6] @D6 ow_RFID_UII_Len
      AND=    vwa_Rcv_Data_Byte[4] H7
      MOV     K0 ow_RFID_UID_Len
        [note] 受信UIDバイト数の設定
      MOV     K0 ow_RFID_Data_Len
        [note] 受信バイト数の設定
987   LD      vb_EPC_Cmd
      AND=    vwa_Rcv_Data_Byte[4] H8
      ?OP6104 vwa_Rcv_Data_Byte[6] D0
      DAND    ow_RFID_UII_Len H0FFFF vd_Calc_Dword
      D+      vd_Calc_Dword D0
      MOV     @D0 ow_RFID_Data_Len
      DINC    D0
      BTOW    @D0 @D4 ow_RFID_Data_Len
1012  LD      vb_EPC_Cmd
      AND=    vwa_Rcv_Data_Byte[4] H8
      +       ow_RFID_UII_Len ow_RFID_Data_Len vw_Chk_TID_Len
      +       K3 vw_Chk_TID_Len
      MPS
      AND>    vwa_Rcv_Data_Byte[3] vw_Chk_TID_Len
      DAND    ow_RFID_Data_Len H0FFFF vd_Calc_Dword
      D+      vd_Calc_Dword D0
      MOV     @D0 ow_RFID_UID_Len
      DINC    D0
      BTOW    @D0 @D2 ow_RFID_UID_Len
      MPP
      AND<=   vwa_Rcv_Data_Byte[3] vw_Chk_TID_Len
      MOV     K0 ow_RFID_UID_Len
1050  LD      vb_EPC_Cmd
      RST     vb_EPC_Cmd
; UIDを含まないコマンドの出力ラベル設定
1075  LD      vb_Other_Cmd
      MOV     K0 ow_RFID_UID_Len
        [note] 受信UIDバイト数の設定
      MPS
      AND=    vwa_Rcv_Data_Byte[2] H31
      MOV     K0 ow_RFID_Data_Len
        [note] 受信バイト数の設定
      MOV     vwa_Rcv_Data_Byte[4] ow_UNT_ERR_CODE1
      AND=    vwa_Rcv_Data_Byte[4] H5
      MOV     vwa_Rcv_Data_Byte[5] ow_UNT_ERR_CODE2
      MRD
      AND<>   vwa_Rcv_Data_Byte[2] H31
      MOV     vwa_Rcv_Data_Byte[3] ow_RFID_Data_Len
        [note] 受信バイト数の設定
      MRD
      AND<>   ow_RFID_Res_Type K255
      BTOW    vwa_Rcv_Data_Byte[4] @D4 ow_RFID_Data_Len
        [note] 受信データの設定
      MRD
      AND=    ow_RFID_Res_Type K255
      +       K7 ow_RFID_Data_Len
      BTOW    vwa_Rcv_Data_Byte[0] @D4 ow_RFID_Data_Len
        [note] 受信データの設定
      MPP
      MOV     K0 ow_RFID_UII_Len
        [note] 受信UIIバイト数の設定
      RST     vb_Other_Cmd
; インデックスレジスタ復帰処理
1206  LD      SM400
      MOV     vw_ZTmp1 Z9
      MOV     vw_ZTmp2 Z8
      DMOV    D0 vd_Rcv_Pos
      DMOV    vd_DTmp1 D0
      DMOV    vd_DTmp2 D2
      DMOV    vd_DTmp3 D4
      DMOV    vd_DTmp4 D6
; FB終了処理
1228  LD      vb_Program_End
      MPS
      AND     vb_Tmp_OK
      PLS     FB_OK
      MRD
      AND     vb_Tmp_Error
      PLS     FB_ERROR
      MRD
      AND     vb_Tmp_Unit_Error
      PLS     ob_UNIT_ERROR
      MPP
      RST     vb_Tmp_OK
      RST     vb_Tmp_Error
      RST     vb_Tmp_Unit_Error
      RST     FB_ENO
      RST     vb_Program_End
      RST     vba_Rcv[0]
      RST     vba_Rcv[1]
      RST     vba_Rcv[2]
1265  LD      vb_Tmp_OK
      OR      vb_Tmp_Error
      OR      vb_Tmp_Unit_Error
      SET     vb_Program_End
END_FUNCTION_BLOCK

FUNCTION_BLOCK P+TAKAYA-TR3-C24_CallBuzzer  // ブザーの制御
VAR_INPUT
  FB_EN : BOOL;  (* 実行命令 *)
  iw_Start_IO_No : INT;  (* ユニット装着XYアドレス *)
END_VAR
VAR_OUTPUT
  FB_OK : BOOL;  (* 正常完了 *)
  FB_ERROR : BOOL;  (* 異常完了フラグ *)
  ERROR_ID : INT;  (* エラーコード *)
  FB_ENO : BOOL;  (* 実行状態 *)
END_VAR
VAR
  vb_Program_Init : BOOL;  (* プログラム実行前初期化 *)
  vb_Check_Input : BOOL;  (* 入力範囲判定 *)
  vb_Tmp_Error : BOOL;  (* エラー内部フラグ *)
  vb_Tmp_OK : BOOL;  (* FB完了内部フラグ *)
  vw_Start_IO_No_Tmp : INT;  (* ユニット装着XYアドレス内部 *)
  vb_Tmp_Unit_Error : BOOL;  (* 機器エラー内部フラグ *)
  vb_Program_End : BOOL;  (* FB終了処理内部フラグ *)
END_VAR
VAR_OUTPUT
  ob_UNIT_ERROR : BOOL;  (* 機器異常完了フラグ *)
  ow_UNIT_ERR_CODE : INT;  (* 機器エラーコード *)
END_VAR
VAR
  vwa_Control_Data : ARRAY [0..2] OF INT;  (* コントロールデータ *)
  vb_Sum_Calc : BOOL;  (* SUM計算開始フラグ *)
  vb_Send_Ready : BOOL;  (* 送信準備完了フラグ *)
  vwa_Send_Sum : ARRAY [0..1] OF INT;  (* 送信SUM合計値 *)
  vwa_Buff_Send_Byte : ARRAY [0..8] OF INT;  (* 送信バッファバイト *)
  vba_Send : ARRAY [0..2] OF BOOL;  (* 送信処理フラグ *)
  vw_Buzzer_Type_Tmp : INT;  (* ブザー音内部 *)
END_VAR
VAR_INPUT
  ib_Response_Type : BOOL;  (* 応答要求 *)
  iw_Buzzer_Type : INT;  (* ブザー音 *)
END_VAR
VAR
  vb_Join_Byte : BOOL;  (* バイト単位結合 *)
  vwa_Buff_Send_Word : ARRAY [0..4] OF INT;  (* 送信バッファワード *)
END_VAR
VAR_INPUT
  iw_Channel_No : INT;  (* 入力チャンネル *)
END_VAR
VAR
  vw_Channel_No_Tmp : INT;  (* 入力チャンネル内部 *)
  vw_ZTmp1 : INT;  (* Zデバイス1内部 *)
  vb_Make_Control_Data : BOOL;  (* コントロールデータ生成 *)
END_VAR
; ＊＊＊＊＊＊＊＊＊＊＊＊＊＊＊＊＊＊＊＊
; ＊FB名称:P+TAKAYA-TR3-C24_CallBuzzer
; ＊機能:ブザーの制御
; ＊バージョン:Ver1.00A
; ＊＊＊＊＊＊＊＊＊＊＊＊＊＊＊＊＊＊＊＊
; FB非実行時接点OFF
100   LDI     FB_EN
      RST     vb_Program_Init
      RST     vb_Check_Input
      RST     vb_Join_Byte
      RST     vb_Sum_Calc
      RST     vb_Make_Control_Data
      RST     vb_Send_Ready
; FB実行開始時
122   LDP     FB_EN
      SET     FB_ENO
      SET     vb_Program_Init
; プログラム実行前初期化
142   LD      vb_Program_Init
      MOV     K0 ERROR_ID
      MOV     K0 ow_UNIT_ERR_CODE
      MOV     K0 vw_Channel_No_Tmp
      MOV     K0 vw_Buzzer_Type_Tmp
      FMOV    K0 vwa_Buff_Send_Byte[0] K9
      FMOV    K0 vwa_Buff_Send_Word[0] K5
      FMOV    K0 vwa_Control_Data[0] K3
      FMOV    K0 vwa_Send_Sum[0] K2
      SET     vb_Check_Input
      RST     vb_Program_Init
; 入力範囲判定
180   LD      vb_Check_Input
      MPS
      LD<     iw_Channel_No K1
      OR>     iw_Channel_No K2
      ANB
      SET     vb_Tmp_Error
      MOV     K120 ERROR_ID
      MRD
      LD<     iw_Buzzer_Type K0
      OR>     iw_Buzzer_Type K8
      ANB
      SET     vb_Tmp_Error
      MOV     K107 ERROR_ID
      MRD
      ANI     vb_Tmp_Error
      MOV     iw_Channel_No vw_Channel_No_Tmp
      MOV     iw_Start_IO_No vw_Start_IO_No_Tmp
      MOV     iw_Buzzer_Type vw_Buzzer_Type_Tmp
      SET     vba_Send[0]
      MPP
      RST     vb_Check_Input
; インデックスレジスタ一時退避
236   LD      SM400
      MOV     Z9 vw_ZTmp1
      MOV     K0 Z9
; インデックスレジスタ値格納
256   LD      FB_ENO
      MOV     vw_Start_IO_No_Tmp Z9
      SFR     Z9 K4
; 送信フォーマット作成
276   LD      vba_Send[0]
      MOV     H2 vwa_Buff_Send_Byte[0]
      MOV     H0 vwa_Buff_Send_Byte[1]
      MOV     H42 vwa_Buff_Send_Byte[2]
      MOV     H2 vwa_Buff_Send_Byte[3]
      MPS
      AND     ib_Response_Type
      MOV     K1 vwa_Buff_Send_Byte[4]
      MPP
      MOV     vw_Buzzer_Type_Tmp vwa_Buff_Send_Byte[5]
      MOV     H3 vwa_Buff_Send_Byte[6]
      MOV     H0D vwa_Buff_Send_Byte[8]
      SET     vb_Sum_Calc
      RST     vba_Send[0]
; SUMの計算
309   LD      vb_Sum_Calc
      WSUM    vwa_Buff_Send_Byte[0] vwa_Send_Sum[0] K7
      DAND    H0FF vwa_Send_Sum[0]
      MOV     vwa_Send_Sum[0] vwa_Buff_Send_Byte[7]
      SET     vb_Join_Byte
      RST     vb_Sum_Calc
; バイト単位データ結合
337   LD      vb_Join_Byte
      BTOW    vwa_Buff_Send_Byte[0] vwa_Buff_Send_Word[0] K9
      SET     vb_Make_Control_Data
      RST     vb_Join_Byte
; コントロールデータ生成
360   LD      vb_Make_Control_Data
      MOV     vw_Channel_No_Tmp vwa_Control_Data[0]
      MOV     K9 vwa_Control_Data[2]
      SET     vb_Send_Ready
      RST     vb_Make_Control_Data
; 送信処理
376   LD      vb_Send_Ready
      GP.OUTPUT U0Z9 vwa_Control_Data[0] vwa_Buff_Send_Word[0] vba_Send[1]
; 正常完了かチェック
400   LD      vba_Send[1]
      MPS
      ANI     vba_Send[2]
      SET     vb_Tmp_OK
      MRD
      AND     vba_Send[2]
      MOV     K119 ERROR_ID
      SET     vb_Tmp_Error
      MOV     vwa_Control_Data[1] ow_UNIT_ERR_CODE
      SET     vb_Tmp_Unit_Error
      MPP
      RST     vb_Send_Ready
; インデックスレジスタ復帰処理
437   LD      SM400
      MOV     vw_ZTmp1 Z9
; FB完了処理
447   LD      vb_Program_End
      MPS
      AND     vb_Tmp_OK
      PLS     FB_OK
      MRD
      AND     vb_Tmp_Error
      PLS     FB_ERROR
      MRD
      AND     vb_Tmp_Unit_Error
      PLS     ob_UNIT_ERROR
      MPP
      RST     vb_Tmp_OK
      RST     vb_Tmp_Error
      RST     vb_Tmp_Unit_Error
      RST     FB_ENO
      RST     vb_Program_End
      RST     vba_Send[0]
      RST     vba_Send[1]
      RST     vba_Send[2]
484   LD      vb_Tmp_OK
      OR      vb_Tmp_Error
      OR      vb_Tmp_Unit_Error
      SET     vb_Program_End
END_FUNCTION_BLOCK

FUNCTION_BLOCK P+TAKAYA-TR3-C24_Inventory2  // Inventory2
VAR_INPUT
  FB_EN : BOOL;  (* 実行命令 *)
END_VAR
VAR_OUTPUT
  FB_OK : BOOL;  (* 正常完了 *)
  FB_ERROR : BOOL;  (* 異常完了フラグ *)
  ERROR_ID : INT;  (* エラーコード *)
  FB_ENO : BOOL;  (* 実行状態 *)
END_VAR
VAR
  vb_Program_Init : BOOL;  (* プログラム実行前初期化 *)
  vb_Check_Input : BOOL;  (* 入力範囲判定 *)
  vb_Tmp_Error : BOOL;  (* エラー内部フラグ *)
  vb_Tmp_OK : BOOL;  (* FB完了内部フラグ *)
  vb_Tmp_Unit_Error : BOOL;  (* 機器エラー内部フラグ *)
  vb_Program_End : BOOL;  (* FB終了処理内部フラグ *)
END_VAR
VAR_OUTPUT
  ob_UNIT_ERROR : BOOL;  (* 機器異常完了フラグ *)
  ow_UNIT_ERR_CODE : INT;  (* 機器エラーコード *)
END_VAR
VAR
  vwa_Control_Data : ARRAY [0..2] OF INT;  (* コントロールデータ *)
  vb_Sum_Calc : BOOL;  (* SUM計算開始フラグ *)
  vb_Send_Ready : BOOL;  (* 送信準備完了フラグ *)
  vwa_Send_Sum : ARRAY [0..1] OF INT;  (* 送信SUM合計値 *)
  vba_Send : ARRAY [0..2] OF BOOL;  (* 送信処理フラグ *)
  vb_RFID_Option : BOOL;  (* RFタグオプションフラグ *)
  vw_RFID_Option_Tmp : INT;  (* RFタグオプション *)
  vb_Join_Byte : BOOL;  (* バイト単位結合 *)
  vwa_Buff_Send_Byte : ARRAY [0..9] OF INT;  (* 送信バッファバイト *)
  vwa_Buff_Send_Word : ARRAY [0..4] OF INT;  (* 送信バッファワード *)
END_VAR
VAR_INPUT
  ib_AFI_Flag : BOOL;  (* AFI指定 *)
  ib_UID_Response : BOOL;  (* UIDレスポンス *)
  iw_Start_IO_No : INT;  (* ユニット装着XYアドレス *)
  iw_Channel_No : INT;  (* 入力チャンネル *)
END_VAR
VAR
  vw_Start_IO_No_Tmp : INT;  (* ユニット装着XYアドレス内部 *)
  vw_Channel_No_Tmp : INT;  (* 入力チャンネル内部 *)
  vw_ZTmp1 : INT;  (* Zデバイス1内部 *)
  vb_Make_Control_Data : BOOL;  (* コントロールデータ生成 *)
END_VAR
; ＊＊＊＊＊＊＊＊＊＊＊＊＊＊＊＊＊＊＊＊
; ＊FB名称:P+TAKAYA-TR3-C24_Inventory2
; ＊機能:Inventory2
; ＊バージョン:Ver1.00A
; ＊＊＊＊＊＊＊＊＊＊＊＊＊＊＊＊＊＊＊＊
; FB非実行時接点OFF
99    LDI     FB_EN
      RST     vb_Program_Init
      RST     vb_Check_Input
      RST     vb_Join_Byte
      RST     vb_RFID_Option
      RST     vb_Sum_Calc
      RST     vb_Make_Control_Data
      RST     vb_Send_Ready
; FB実行開始時
123   LDP     FB_EN
      SET     FB_ENO
      SET     vb_Program_Init
; プログラム実行前初期化
143   LD      vb_Program_Init
      MOV     K0 ERROR_ID
      MOV     K0 ow_UNIT_ERR_CODE
      MOV     K0 vw_Channel_No_Tmp
      MOV     K0 vw_RFID_Option_Tmp
      FMOV    K0 vwa_Buff_Send_Byte[0] K10
      FMOV    K0 vwa_Buff_Send_Word[0] K5
      FMOV    K0 vwa_Control_Data[0] K3
      FMOV    K0 vwa_Send_Sum[0] K2
      SET     vb_Check_Input
      RST     vb_Program_Init
; 入力範囲判定
181   LD      vb_Check_Input
      MPS
      LD<     iw_Channel_No K1
      OR>     iw_Channel_No K2
      ANB
      SET     vb_Tmp_Error
      MOV     K120 ERROR_ID
      MRD
      ANI     vb_Tmp_Error
      MOV     iw_Channel_No vw_Channel_No_Tmp
      MOV     iw_Start_IO_No vw_Start_IO_No_Tmp
      SET     vba_Send[0]
      MPP
      RST     vb_Check_Input
; インデックスレジスタ一時退避
223   LD      SM400
      MOV     Z9 vw_ZTmp1
      MOV     K0 Z9
; インデックスレジスタ値格納
243   LD      FB_ENO
      MOV     vw_Start_IO_No_Tmp Z9
      SFR     Z9 K4
; 送信フォーマット作成
263   LD      vba_Send[0]
      MOV     H2 vwa_Buff_Send_Byte[0]
      MOV     H0 vwa_Buff_Send_Byte[1]
      MOV     H78 vwa_Buff_Send_Byte[2]
      MOV     H3 vwa_Buff_Send_Byte[3]
      MOV     H0F0 vwa_Buff_Send_Byte[4]
      MPS
      AND     ib_UID_Response
      MOV     H1 vwa_Buff_Send_Byte[6]
      MPP
      MOV     H3 vwa_Buff_Send_Byte[7]
      MOV     H0D vwa_Buff_Send_Byte[9]
      SET     vb_RFID_Option
      RST     vba_Send[0]
; RFタグのオプション設定
302   LD      vb_RFID_Option
      MPS
      AND     ib_AFI_Flag
      BSET    vw_RFID_Option_Tmp K5
      MPP
      MOV     vw_RFID_Option_Tmp vwa_Buff_Send_Byte[5]
      SET     vb_Sum_Calc
      RST     vb_RFID_Option
; SUMの計算
324   LD      vb_Sum_Calc
      WSUM    vwa_Buff_Send_Byte[0] vwa_Send_Sum[0] K8
      DAND    H0FF vwa_Send_Sum[0]
      MOV     vwa_Send_Sum[0] vwa_Buff_Send_Byte[8]
      SET     vb_Join_Byte
      RST     vb_Sum_Calc
; バイト単位データ結合
352   LD      vb_Join_Byte
      BTOW    vwa_Buff_Send_Byte[0] vwa_Buff_Send_Word[0] K10
      SET     vb_Make_Control_Data
      RST     vb_Join_Byte
; コントロールデータ生成
375   LD      vb_Make_Control_Data
      MOV     vw_Channel_No_Tmp vwa_Control_Data[0]
      MOV     K10 vwa_Control_Data[2]
      SET     vb_Send_Ready
      RST     vb_Make_Control_Data
; 送信処理
391   LD      vb_Send_Ready
      GP.OUTPUT U0Z9 vwa_Control_Data[0] vwa_Buff_Send_Word[0] vba_Send[1]
; 正常完了かチェック
415   LD      vba_Send[1]
      MPS
      ANI     vba_Send[2]
      SET     vb_Tmp_OK
      MRD
      AND     vba_Send[2]
      MOV     K119 ERROR_ID
      SET     vb_Tmp_Error
      MOV     vwa_Control_Data[1] ow_UNIT_ERR_CODE
      SET     vb_Tmp_Unit_Error
      MPP
      RST     vb_Send_Ready
; インデックスレジスタ復帰処理
452   LD      SM400
      MOV     vw_ZTmp1 Z9
; FB完了処理
462   LD      vb_Program_End
      MPS
      AND     vb_Tmp_OK
      PLS     FB_OK
      MRD
      AND     vb_Tmp_Error
      PLS     FB_ERROR
      MRD
      AND     vb_Tmp_Unit_Error
      PLS     ob_UNIT_ERROR
      MPP
      RST     vb_Tmp_OK
      RST     vb_Tmp_Error
      RST     vb_Tmp_Unit_Error
      RST     FB_ENO
      RST     vb_Program_End
      RST     vba_Send[0]
      RST     vba_Send[1]
      RST     vba_Send[2]
499   LD      vb_Tmp_OK
      OR      vb_Tmp_Error
      OR      vb_Tmp_Unit_Error
      SET     vb_Program_End
END_FUNCTION_BLOCK

FUNCTION_BLOCK P+TAKAYA-TR3-C24_ReadBytes  // ReadBytes
VAR_INPUT
  FB_EN : BOOL;  (* 実行命令 *)
END_VAR
VAR_OUTPUT
  FB_OK : BOOL;  (* 正常完了 *)
  FB_ERROR : BOOL;  (* 異常完了フラグ *)
  ERROR_ID : INT;  (* エラーコード *)
  FB_ENO : BOOL;  (* 実行状態 *)
END_VAR
VAR
  vb_Program_Init : BOOL;  (* プログラム実行前初期化 *)
  vb_Check_Input : BOOL;  (* 入力範囲判定 *)
  vb_Tmp_Error : BOOL;  (* エラー内部フラグ *)
  vb_Tmp_OK : BOOL;  (* FB完了内部フラグ *)
  vb_Tmp_Unit_Error : BOOL;  (* 機器エラー内部フラグ *)
  vb_Program_End : BOOL;  (* FB終了処理内部フラグ *)
END_VAR
VAR_OUTPUT
  ob_UNIT_ERROR : BOOL;  (* 機器異常完了フラグ *)
  ow_UNIT_ERR_CODE : INT;  (* 機器エラーコード *)
END_VAR
VAR
  vwa_Control_Data : ARRAY [0..2] OF INT;  (* コントロールデータ *)
  vb_Sum_Calc : BOOL;  (* SUM計算開始フラグ *)
  vb_Send_Ready : BOOL;  (* 送信準備完了フラグ *)
  vwa_Send_Sum : ARRAY [0..1] OF INT;  (* 送信SUM合計値 *)
  vba_Send : ARRAY [0..2] OF BOOL;  (* 送信処理フラグ *)
  vb_RFID_Option : BOOL;  (* RFタグオプションフラグ *)
  vw_RFID_Option_Tmp : INT;  (* RFタグオプション *)
  vb_Join_Byte : BOOL;  (* バイト単位結合 *)
  vwa_Buff_Send_Byte : ARRAY [0..18] OF INT;  (* 送信バッファバイト *)
  vwa_Buff_Send_Word : ARRAY [0..9] OF INT;  (* 送信バッファワード *)
END_VAR
VAR_INPUT
  iwa_UID : INT;  (* UID *)
  ib_UID_Flag : BOOL;  (* UID指定 *)
END_VAR
VAR
  vw_Byte_Size_Tmp : INT;  (* 読み取りバイト数内部 *)
  vwa_UID_Tmp : ARRAY [0..7] OF INT;  (* UID内部 *)
END_VAR
VAR_INPUT
  iw_Byte_Size : INT;  (* 読み取りバイト数 *)
  iw_Start_Blk_No : INT;  (* 読み取り開始ブロック番号 *)
END_VAR
VAR
  vw_Start_Blk_No_Tmp : INT;  (* 読み取り開始ブロック番号内部 *)
END_VAR
VAR_INPUT
  iw_Start_IO_No : INT;  (* ユニット装着XYアドレス *)
  iw_Channel_No : INT;  (* 入力チャンネル *)
END_VAR
VAR
  vw_Start_IO_No_Tmp : INT;  (* ユニット装着XYアドレス内部 *)
  vw_Channel_No_Tmp : INT;  (* 入力チャンネル内部 *)
  vw_ZTmp1 : INT;  (* Zデバイス1内部 *)
  vb_Make_Control_Data : BOOL;  (* コントロールデータ生成 *)
END_VAR
; ＊＊＊＊＊＊＊＊＊＊＊＊＊＊＊＊＊＊＊＊
; ＊FB名称:P+TAKAYA-TR3-C24_ReadBytes
; ＊機能:ReadBytes
; ＊バージョン:Ver1.00A
; ＊＊＊＊＊＊＊＊＊＊＊＊＊＊＊＊＊＊＊＊
; FB非実行時接点OFF
98    LDI     FB_EN
      RST     vb_Program_Init
      RST     vb_Check_Input
      RST     vb_Join_Byte
      RST     vb_RFID_Option
      RST     vb_Sum_Calc
      RST     vb_Make_Control_Data
      RST     vb_Send_Ready
; FB実行開始時
122   LDP     FB_EN
      SET     FB_ENO
      SET     vb_Program_Init
; プログラム実行前初期化
142   LD      vb_Program_Init
      MOV     K0 ERROR_ID
      MOV     K0 ow_UNIT_ERR_CODE
      MOV     K0 vw_Channel_No_Tmp
      MOV     K0 vw_RFID_Option_Tmp
      MOV     K0 vw_Start_Blk_No_Tmp
      MOV     K0 vw_Byte_Size_Tmp
      FMOV    K0 vwa_UID_Tmp[0] K8
      FMOV    K0 vwa_Buff_Send_Byte[0] K19
      FMOV    K0 vwa_Buff_Send_Word[0] K10
      FMOV    K0 vwa_Control_Data[0] K3
      FMOV    K0 vwa_Send_Sum[0] K2
      SET     vb_Check_Input
      RST     vb_Program_Init
; 入力範囲判定
188   LD      vb_Check_Input
      MPS
      LD<     iw_Channel_No K1
      OR>     iw_Channel_No K2
      ANB
      SET     vb_Tmp_Error
      MOV     K120 ERROR_ID
      MRD
      LD<     iw_Start_Blk_No K0
      OR>     iw_Start_Blk_No K255
      ANB
      SET     vb_Tmp_Error
      MOV     K111 ERROR_ID
      MRD
      LD<     iw_Byte_Size K1
      OR>     iw_Byte_Size K254
      ANB
      SET     vb_Tmp_Error
      MOV     K113 ERROR_ID
      MRD
      AND     ib_UID_Flag
      WTOB    iwa_UID vwa_UID_Tmp[0] K8
      MRD
      ANI     vb_Tmp_Error
      MOV     iw_Channel_No vw_Channel_No_Tmp
      MOV     iw_Start_IO_No vw_Start_IO_No_Tmp
      MOV     iw_Start_Blk_No vw_Start_Blk_No_Tmp
      MOV     iw_Byte_Size vw_Byte_Size_Tmp
      SET     vba_Send[0]
      MPP
      RST     vb_Check_Input
; インデックスレジスタ一時退避
265   LD      SM400
      MOV     Z9 vw_ZTmp1
      MOV     K0 Z9
; インデックスレジスタ値格納
285   LD      FB_ENO
      MOV     vw_Start_IO_No_Tmp Z9
      SFR     Z9 K4
; 送信フォーマット作成
305   LD      vba_Send[0]
      MOV     H2 vwa_Buff_Send_Byte[0]
      MOV     H0 vwa_Buff_Send_Byte[1]
      MOV     H78 vwa_Buff_Send_Byte[2]
      MPS
      AND     ib_UID_Flag
      MOV     H0C vwa_Buff_Send_Byte[3]
      MRD
      ANI     ib_UID_Flag
      MOV     H4 vwa_Buff_Send_Byte[3]
      MPP
      MOV     H0A0 vwa_Buff_Send_Byte[4]
      MOV     vw_Start_Blk_No_Tmp vwa_Buff_Send_Byte[5]
      MOV     vw_Byte_Size_Tmp vwa_Buff_Send_Byte[6]
      MPS
      AND     ib_UID_Flag
      BMOV    vwa_UID_Tmp[0] vwa_Buff_Send_Byte[8] K8
      MOV     H3 vwa_Buff_Send_Byte[16]
      MOV     H0D vwa_Buff_Send_Byte[18]
      MRD
      ANI     ib_UID_Flag
      MOV     H3 vwa_Buff_Send_Byte[8]
      MOV     H0D vwa_Buff_Send_Byte[10]
      MPP
      SET     vb_RFID_Option
      RST     vba_Send[0]
; RFタグのオプション設定
366   LD      vb_RFID_Option
      MPS
      AND     ib_UID_Flag
      BSET    vw_RFID_Option_Tmp K0
      MPP
      MOV     vw_RFID_Option_Tmp vwa_Buff_Send_Byte[7]
      SET     vb_Sum_Calc
      RST     vb_RFID_Option
; SUMの計算
388   LD      vb_Sum_Calc
      MPS
      AND     ib_UID_Flag
      WSUM    vwa_Buff_Send_Byte[0] vwa_Send_Sum[0] K17
      MRD
      ANI     ib_UID_Flag
      WSUM    vwa_Buff_Send_Byte[0] vwa_Send_Sum[0] K9
      MPP
      DAND    H0FF vwa_Send_Sum[0]
      MPS
      AND     ib_UID_Flag
      MOV     vwa_Send_Sum[0] vwa_Buff_Send_Byte[17]
      MRD
      ANI     ib_UID_Flag
      MOV     vwa_Send_Sum[0] vwa_Buff_Send_Byte[9]
      MPP
      SET     vb_Join_Byte
      RST     vb_Sum_Calc
; バイト単位データ結合
436   LD      vb_Join_Byte
      MPS
      AND     ib_UID_Flag
      BTOW    vwa_Buff_Send_Byte[0] vwa_Buff_Send_Word[0] K19
      MRD
      ANI     ib_UID_Flag
      BTOW    vwa_Buff_Send_Byte[0] vwa_Buff_Send_Word[0] K11
      MPP
      SET     vb_Make_Control_Data
      RST     vb_Join_Byte
; コントロールデータ生成
470   LD      vb_Make_Control_Data
      MOV     vw_Channel_No_Tmp vwa_Control_Data[0]
      MPS
      AND     ib_UID_Flag
      MOV     K19 vwa_Control_Data[2]
      MRD
      ANI     ib_UID_Flag
      MOV     K11 vwa_Control_Data[2]
      MPP
      SET     vb_Send_Ready
      RST     vb_Make_Control_Data
; 送信処理
495   LD      vb_Send_Ready
      GP.OUTPUT U0Z9 vwa_Control_Data[0] vwa_Buff_Send_Word[0] vba_Send[1]
; 正常完了かチェック
519   LD      vba_Send[1]
      MPS
      ANI     vba_Send[2]
      SET     vb_Tmp_OK
      MRD
      AND     vba_Send[2]
      MOV     K119 ERROR_ID
      SET     vb_Tmp_Error
      MOV     vwa_Control_Data[1] ow_UNIT_ERR_CODE
      SET     vb_Tmp_Unit_Error
      MPP
      RST     vb_Send_Ready
; インデックスレジスタ復帰処理
556   LD      SM400
      MOV     vw_ZTmp1 Z9
; FB完了処理
566   LD      vb_Program_End
      MPS
      AND     vb_Tmp_OK
      PLS     FB_OK
      MRD
      AND     vb_Tmp_Error
      PLS     FB_ERROR
      MRD
      AND     vb_Tmp_Unit_Error
      PLS     ob_UNIT_ERROR
      MPP
      RST     vb_Tmp_OK
      RST     vb_Tmp_Error
      RST     vb_Tmp_Unit_Error
      RST     FB_ENO
      RST     vb_Program_End
      RST     vba_Send[0]
      RST     vba_Send[1]
      RST     vba_Send[2]
603   LD      vb_Tmp_OK
      OR      vb_Tmp_Error
      OR      vb_Tmp_Unit_Error
      SET     vb_Program_End
END_FUNCTION_BLOCK

FUNCTION_BLOCK P+TAKAYA-TR3-C24_SetTransmitSig  // RF送信信号の制御
VAR_INPUT
  FB_EN : BOOL;  (* 実行命令 *)
  iw_Start_IO_No : INT;  (* ユニット装着XYアドレス *)
END_VAR
VAR_OUTPUT
  FB_OK : BOOL;  (* 正常完了 *)
  FB_ERROR : BOOL;  (* 異常完了フラグ *)
  ERROR_ID : INT;  (* エラーコード *)
  FB_ENO : BOOL;  (* 実行状態 *)
END_VAR
VAR
  vb_Program_Init : BOOL;  (* プログラム実行前初期化 *)
  vb_Check_Input : BOOL;  (* 入力範囲判定 *)
  vb_Tmp_Error : BOOL;  (* エラー内部フラグ *)
  vb_Tmp_OK : BOOL;  (* FB完了内部フラグ *)
  vw_Start_IO_No_Tmp : INT;  (* ユニット装着XYアドレス内部 *)
  vb_Tmp_Unit_Error : BOOL;  (* 機器エラー内部フラグ *)
  vb_Program_End : BOOL;  (* FB終了処理内部フラグ *)
END_VAR
VAR_OUTPUT
  ob_UNIT_ERROR : BOOL;  (* 機器異常完了フラグ *)
  ow_UNIT_ERR_CODE : INT;  (* 機器エラーコード *)
END_VAR
VAR
  vwa_Conｔrol_Data : ARRAY [0..2] OF INT;  (* コントロールデータ *)
  vb_Sum_Calc : BOOL;  (* SUM計算開始フラグ *)
  vb_Send_Ready : BOOL;  (* 送信準備完了フラグ *)
  vw_Send_Sum : ARRAY [0..1] OF INT;  (* 送信SUM合計値 *)
  vwa_Buff_Send_Byte : ARRAY [0..8] OF INT;  (* 送信バッファバイト *)
  vba_Send : ARRAY [0..2] OF BOOL;  (* 送信処理フラグ *)
  vw_Transmit_Sig_Tmp : INT;  (* 送信信号設定内部 *)
  vb_Join_Byte : BOOL;  (* バイト単位結合 *)
  vwa_Buff_Send_Word : ARRAY [0..4] OF INT;  (* 送信バッファワード *)
  vw_Channel_No_Tmp : INT;  (* 入力チャンネル内部 *)
END_VAR
VAR_INPUT
  iw_Transmit_Sig : INT;  (* 送信信号設定 *)
  iw_Channel_No : INT;  (* 入力チャンネル *)
END_VAR
VAR
  vb_Make_Conｔrol_Data : BOOL;  (* コントロールデータ生成 *)
  vw_ZTmp1 : INT;  (* Zデバイス1内部 *)
END_VAR
; ＊＊＊＊＊＊＊＊＊＊＊＊＊＊＊＊＊＊＊＊
; ＊FB名称:P+TAKAYA-TR3-C24_SetTransmitSig
; ＊機能:RF送信信号の制御
; ＊バージョン:Ver1.00A
; ＊＊＊＊＊＊＊＊＊＊＊＊＊＊＊＊＊＊＊＊
; FB非実行時接点OFF
104   LDI     FB_EN
      RST     vb_Program_Init
      RST     vb_Check_Input
      RST     vb_Join_Byte
      RST     vb_Sum_Calc
      RST     vb_Make_Conｔrol_Data
      RST     vb_Send_Ready
; FB実行開始時
126   LDP     FB_EN
      SET     FB_ENO
      SET     vb_Program_Init
; プログラム実行前初期化
146   LD      vb_Program_Init
      MOV     K0 ERROR_ID
      MOV     K0 ow_UNIT_ERR_CODE
      MOV     K0 vw_Channel_No_Tmp
      MOV     K0 vw_Transmit_Sig_Tmp
      FMOV    K0 vwa_Buff_Send_Byte[0] K9
      FMOV    K0 vwa_Buff_Send_Word[0] K5
      FMOV    K0 vwa_Conｔrol_Data[0] K3
      FMOV    K0 vw_Send_Sum[0] K2
      SET     vb_Check_Input
      RST     vb_Program_Init
; 入力範囲判定
184   LD      vb_Check_Input
      MPS
      LD<     iw_Channel_No K1
      OR>     iw_Channel_No K2
      ANB
      SET     vb_Tmp_Error
      MOV     K120 ERROR_ID
      MRD
      LD<     iw_Transmit_Sig K0
      OR>     iw_Transmit_Sig K2
      ANB
      SET     vb_Tmp_Error
      MOV     K101 ERROR_ID
      MRD
      ANI     vb_Tmp_Error
      MOV     iw_Channel_No vw_Channel_No_Tmp
      MOV     iw_Start_IO_No vw_Start_IO_No_Tmp
      MOV     iw_Transmit_Sig vw_Transmit_Sig_Tmp
      SET     vba_Send[0]
      MPP
      RST     vb_Check_Input
; インデックスレジスタ一時退避
240   LD      SM400
      MOV     Z9 vw_ZTmp1
      MOV     K0 Z9
; インデックスレジスタ値格納
260   LD      FB_ENO
      MOV     vw_Start_IO_No_Tmp Z9
      SFR     Z9 K4
; 送信フォーマット作成
280   LD      vba_Send[0]
      MOV     H2 vwa_Buff_Send_Byte[0]
      MOV     H0 vwa_Buff_Send_Byte[1]
      MOV     H4E vwa_Buff_Send_Byte[2]
      MOV     H2 vwa_Buff_Send_Byte[3]
      MOV     H9E vwa_Buff_Send_Byte[4]
      MOV     vw_Transmit_Sig_Tmp vwa_Buff_Send_Byte[5]
      MOV     H3 vwa_Buff_Send_Byte[6]
      MOV     H0D vwa_Buff_Send_Byte[8]
      SET     vb_Sum_Calc
      RST     vba_Send[0]
; SUMの計算
309   LD      vb_Sum_Calc
      WSUM    vwa_Buff_Send_Byte[0] vw_Send_Sum[0] K7
      DAND    H0FF vw_Send_Sum[0]
      MOV     vw_Send_Sum[0] vwa_Buff_Send_Byte[7]
      SET     vb_Join_Byte
      RST     vb_Sum_Calc
; バイト単位データ結合
337   LD      vb_Join_Byte
      BTOW    vwa_Buff_Send_Byte[0] vwa_Buff_Send_Word[0] K9
      SET     vb_Make_Conｔrol_Data
      RST     vb_Join_Byte
; コントロールデータ生成
360   LD      vb_Make_Conｔrol_Data
      MOV     vw_Channel_No_Tmp vwa_Conｔrol_Data[0]
      MOV     K9 vwa_Conｔrol_Data[2]
      SET     vb_Send_Ready
      RST     vb_Make_Conｔrol_Data
; 送信処理
376   LD      vb_Send_Ready
      GP.OUTPUT U0Z9 vwa_Conｔrol_Data[0] vwa_Buff_Send_Word[0] vba_Send[1]
; 正常完了かチェック
400   LD      vba_Send[1]
      MPS
      ANI     vba_Send[2]
      SET     vb_Tmp_OK
      MRD
      AND     vba_Send[2]
      MOV     K119 ERROR_ID
      SET     vb_Tmp_Error
      MOV     vwa_Conｔrol_Data[1] ow_UNIT_ERR_CODE
      SET     vb_Tmp_Unit_Error
      MPP
      RST     vb_Send_Ready
; インデックスレジスタ復帰処理
437   LD      SM400
      MOV     vw_ZTmp1 Z9
; FB完了処理
447   LD      vb_Program_End
      MPS
      AND     vb_Tmp_OK
      PLS     FB_OK
      MRD
      AND     vb_Tmp_Error
      PLS     FB_ERROR
      MRD
      AND     vb_Tmp_Unit_Error
      PLS     ob_UNIT_ERROR
      MPP
      RST     vb_Tmp_OK
      RST     vb_Tmp_Error
      RST     vb_Tmp_Unit_Error
      RST     FB_ENO
      RST     vb_Program_End
      RST     vba_Send[0]
      RST     vba_Send[1]
      RST     vba_Send[2]
484   LD      vb_Tmp_OK
      OR      vb_Tmp_Error
      OR      vb_Tmp_Unit_Error
      SET     vb_Program_End
END_FUNCTION_BLOCK

// device comments not shown above
Y12  ; 読取処理中
